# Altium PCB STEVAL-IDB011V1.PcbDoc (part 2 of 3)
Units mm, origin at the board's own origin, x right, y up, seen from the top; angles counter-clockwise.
Board outline 80.36 x 54.03 mm, 4 copper layers (Top Layer, Mid-Layer 1, Mid-Layer 2, Bottom Layer), stack 1.697 mm thick; 155 components, 122 nets, 506 pads, 646 vias.

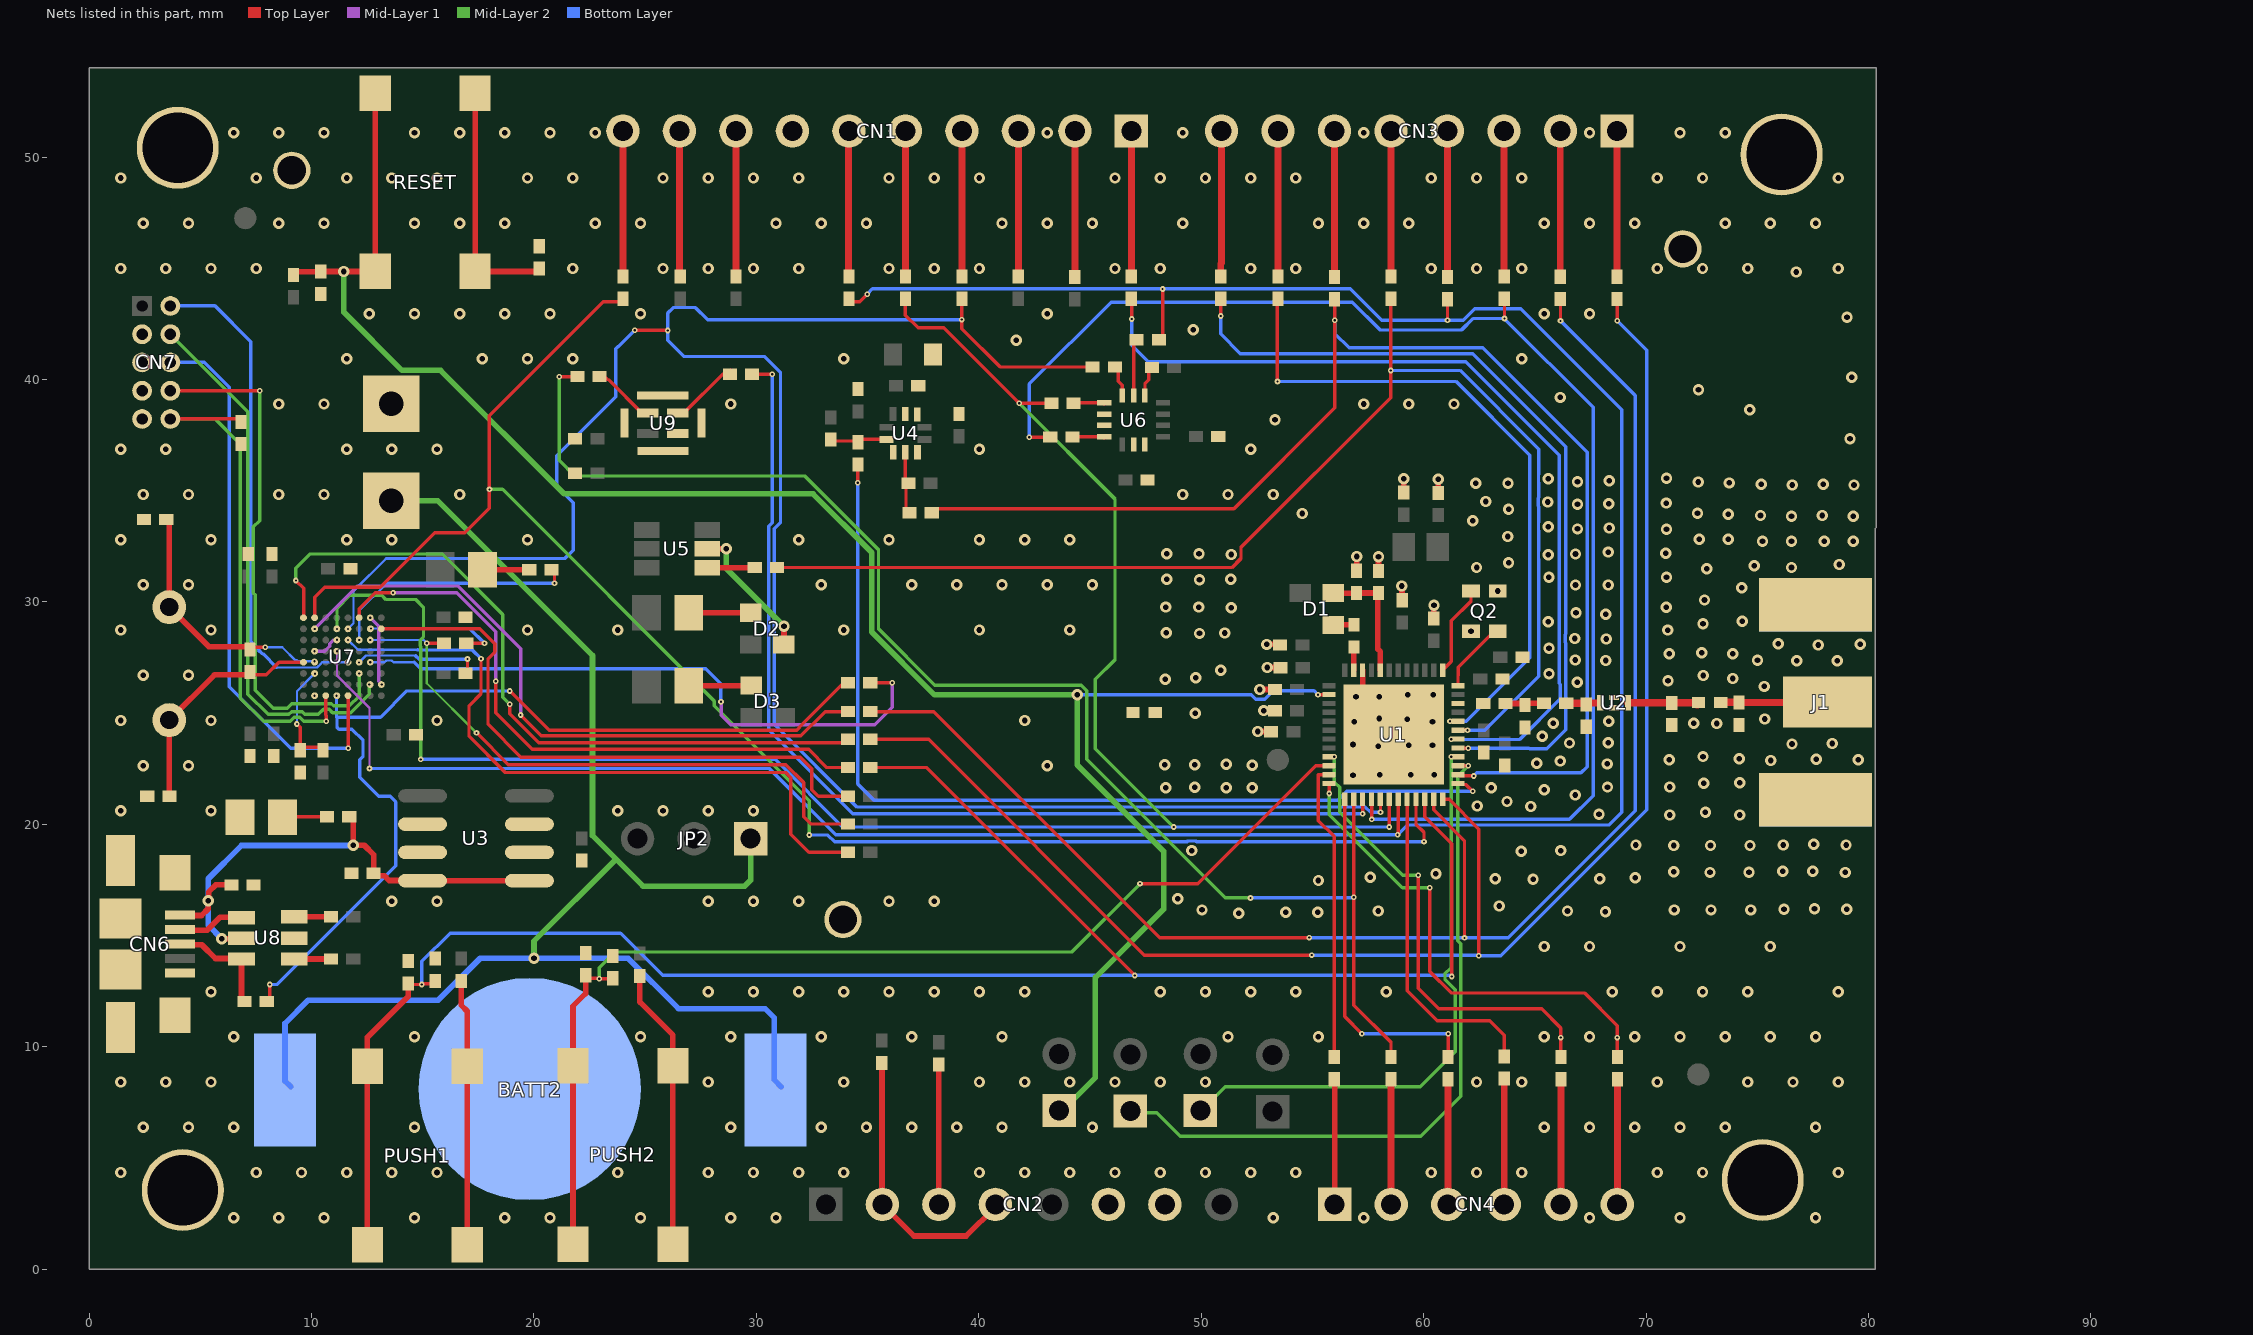
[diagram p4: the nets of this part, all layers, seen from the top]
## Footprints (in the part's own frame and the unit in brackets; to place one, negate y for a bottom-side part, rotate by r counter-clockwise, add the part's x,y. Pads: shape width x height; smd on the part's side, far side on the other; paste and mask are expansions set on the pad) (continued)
PCBCOMPONENT_1 [mil]
  round 12 smd paste+0 mask+0: A1(68.95,-68.95) A2(49.25,-68.95) A3(29.55,-68.95) A4(9.85,-68.95) A5(-9.85,-68.95) A6(-29.55,-68.95) A7(-49.25,-68.95) A8(-68.95,-68.95) B1(68.95,-49.25) B2(49.25,-49.25) B3(29.55,-49.25) B4(9.85,-49.25) B5(-9.85,-49.25) B6(-29.55,-49.25) B7(-49.25,-49.25) B8(-68.95,-49.25) C1(68.95,-29.55) C2(49.25,-29.55) C3(29.55,-29.55) C4(9.85,-29.55) C5(-9.85,-29.55) C6(-29.55,-29.55) C7(-49.25,-29.55) C8(-68.95,-29.55) D1(68.95,-9.85) D2(49.25,-9.85) D3(29.55,-9.85) D4(9.85,-9.85) D5(-9.85,-9.85) D6(-29.55,-9.85) D7(-49.25,-9.85) D8(-68.95,-9.85) E1(68.95,9.85) E2(49.25,9.85) E3(29.55,9.85) E4(9.85,9.85) E5(-9.85,9.85) E6(-29.55,9.85) E7(-49.25,9.85) E8(-68.95,9.85) F1(68.95,29.55) F2(49.25,29.55) F3(29.55,29.55) F4(9.85,29.55) F5(-9.85,29.55) F6(-29.55,29.55) F7(-49.25,29.55) F8(-68.95,29.55) G1(68.95,49.25) G2(49.25,49.25) G3(29.55,49.25) G4(9.85,49.25) G5(-9.85,49.25) G6(-29.55,49.25) G7(-49.25,49.25) G8(-68.95,49.25) H1(68.95,68.95) H2(49.25,68.95) H3(29.55,68.95) H4(9.85,68.95) H5(-9.85,68.95) H6(-29.55,68.95) H7(-49.25,68.95) H8(-68.95,68.95)
  silkscreen extent -98,-97 98,97, body extent -75,-75 75,75, height 20
QFN48_6X6 [mm]
  rect 0.599x0.24 smd: 1(-2.61,1.9) 2(-2.61,1.5) 3(-2.61,1.1) 4(-2.61,0.7) 5(-2.61,0.3) 6(-2.61,-0.1) 7(-2.61,-0.5) 8(-2.61,-0.9) 9(-2.61,-1.3) 10(-2.61,-1.7) 11(-2.61,-2.1) 12(-2.61,-2.5) 25(3.19,-2.5) 26(3.19,-2.1) 27(3.19,-1.7) 28(3.19,-1.3) 29(3.19,-0.9) 30(3.19,-0.5) 31(3.19,-0.1) 32(3.19,0.3) 33(3.19,0.7) 34(3.19,1.1) 35(3.19,1.5) 36(3.19,1.9)
  rect 0.24x0.599 smd: 13(-1.9,-3.19) 14(-1.5,-3.19) 15(-1.1,-3.19) 16(-0.7,-3.19) 17(-0.3,-3.19) 18(0.1,-3.19) 19(0.5,-3.19) 20(0.9,-3.19) 21(1.3,-3.19) 22(1.7,-3.19) 23(2.1,-3.19) 24(2.5,-3.19) 37(2.5,2.61) 38(2.1,2.61) 39(1.7,2.61) 40(1.3,2.61) 41(0.9,2.61) 42(0.5,2.61) 43(0.1,2.61) 44(-0.3,2.61) 45(-0.7,2.61) 46(-1.1,2.61) 47(-1.5,2.61) 48(-1.9,2.61)
  rect 4.499x4.499 smd: 49(0.3,-0.3)
  body extent -2.91,-3.49 3.49,2.91, height 0.51
QUARZO [mil]
  round 60 hole 32: 1(0,0) 2(200,0)
  silkscreen extent -99,-94 299,94, body extent -103,-98 303,98, height 80
"SMA Johonson 142-0701-841" [mm] "50 Ohms, SMA Jack Receptacle, Edge Mount, .25µm Gold (Au) Plating"
  rect 4x2.29 smd paste-4 mask+0: 1(0,0)
  rect 5.08x2.415 smd paste-4 mask+0: 2(0.54,4.383) 2(0.54,-4.383)
  rect 5.05x2.415 smd far side paste-4 mask+0: 2(0.54,4.383)
  rect 5.08x2.415 smd far side paste-4 mask+0: 2(0.54,-4.383)
  silkscreen extent -11.68,-4.7 -2.29,4.57, body extent -13.29,-4.77 2.25,4.76, height 8.5
"SMD _LED" [mm]
  rect 1.3x1.6 smd: 1(0.948,0.006) 2(-0.952,0.006)
  silkscreen extent -2.13,-1.14 2,1.16, body extent -1.52,-0.64 1.52,0.64, height 1.27
SO8_N [mm] "SOIC, 8-Leads, Body 4.9x3.9mm, Pitch 1.27mm, IPC Medium Density"
  oval 2.2x0.6 smd: 1(-2.4,1.905) 2(-2.4,0.635) 3(-2.4,-0.635) 4(-2.4,-1.905) 5(2.4,-1.905) 6(2.4,-0.635) 7(2.4,0.635) 8(2.4,1.905)
  silkscreen extent -2.52,-2.5 0.9,2.88, body extent -1.95,-2.45 1.95,2.45, height 1.75
SOT23-6L_S [mil]
  rect 23.6x47.23 smd: 1(-37,-42.12) 2(0,-42.12) 3(37.8,-42.12) 4(36.22,51.18) 5(0,51.17) 6(-37,51.17)
  silkscreen extent -78,-55 55,22, body extent -49,-66 50,75, height 20
stlogo [mm]
TESTP [mil]
  round 66 hole 50: 1(-50,100)

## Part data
BATT2: library part "Battery holder_0"
C1 C2 C3 C4 C5 C6 C7 C8 C9 C10 C11 C12 C13 C14 C15 C16 C17 C18 C19 C27 C28 C30 C31 C32 C33 C34 C35 C36 C39 C42 C43: library part "MURATA GRM36"
C20 C21 C22 C23 C24 C25 C26 C29 C37 C38 C40 C41: library part C, PSpiceTemplate="C^@REFDES %1 %2 ?TOLERANCE[]C^@REFDES[] @VALUE ?IC/IC{}@IC/ ?TOLERANCE[]\n.model C^@REFDES CAP C{}1 DEV{}@TOLERANCE%[]"
CN6: library part "USB micro B_0"
CN7: library part CON10AP
D1 D2 D3: library part DEV3L_0
DL3 DL4: library part Diodo_led
J1: library part SMA_Molex, "50 Ohms, SMA Jack Receptacle, Edge Mount, .25µm Gold (Au) Plating", Manufacturer=Molex
JP1 JP3 JP4 JP5: library part Buzzer
L1 L2 L3 L4: library part IND_short
PUSH1 PUSH2 RESET: library part SWITCH-1
Q1: library part QUARZO
Q2: library part NX3225SA
R1 R2 R3 R4 R5 R6 R7 R8 R9 R10 R11 R12 R13 R14 R15 R16 R17 R18 R19 R20 R21 R22 R23 R24 R25 R26 R27 R28 R30 R31 R32 R33 R35 R37 R38 R39 R41 R42 R43 R44 R45 R46 R47 R48 R49 R50 R51 R52 R53 R54 R55 R56 R57 R58 R59 R60 R61: library part R_Dup1, PSpiceTemplate="R^@REFDES %1 %2 ?TOLERANCE[]R^@REFDES[] @VALUE  ?TOLERANCE[]\n.model R^@REFDES RES R{}1 DEV{}@TOLERANCE%[]"
R29 R34 R36 R40: library part R
ST1: library part STlogo
TP1 TP2 TP3 TP4: library part "T POINT R"
U1: library part BlueNRG-LP_QFN48_0
U2: library part DLF162500LT
U3: library part KF15BD, "Very Low Drop Voltage Regulator with Inhibit", Package="SOT-23-5 STMicroelectronics"
U4: library part LPS25HB
U7: library part STM32F10XRXY, "No Description Available"
U8: library part USBUFxxW6_0
U9: library part MP34DT05-A_0
X1: library part QUARZO_Dup1

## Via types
v1: diameter 0.508, hole 0.254, Top Layer to Bottom Layer, tented both sides, 518 vias
v2: diameter 0.254, hole 0.102, Top Layer to Bottom Layer, tented both sides, 128 vias

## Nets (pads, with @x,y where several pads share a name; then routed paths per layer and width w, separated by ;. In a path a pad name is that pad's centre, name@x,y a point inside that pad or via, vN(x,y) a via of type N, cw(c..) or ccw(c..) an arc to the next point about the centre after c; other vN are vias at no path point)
BLE_RSTN: C20.2 JP5.1 R26.2 RESET.3 RESET.4 U1.38 | length 89.7
  Top Layer w0.102: R26.2@9.195,44.831 R26.2@9.212,44.848 ; C20.2@10.414,44.848 C20.2@10.422,44.856 ; RESET.4@12.866,44.856 RESET.4@12.867,44.858
  Top Layer w0.152: v2(55.251,25.833) 55.252,25.834 55.744,25.834 U1.38@55.746,25.836
  Top Layer w0.254: R26.2@9.212,44.848 C20.2@10.414,44.848 ; C20.2@10.422,44.856 v1(11.455,44.856) ; v1@11.457,44.858 11.459,44.856 RESET.4@12.866,44.856 ; RESET.4@12.867,44.858 RESET.3@12.867,52.868
  Mid-Layer 2 w0.254: v1(11.455,44.856) 11.455,43.029 14.073,40.411 15.809,40.411 21.364,34.856 32.555,34.856 35.189,32.222 35.189,28.651 38.019,25.822 v1(44.422,25.822) 44.422,22.68 48.316,18.786 48.316,16.187 45.242,13.114 45.242,8.616 JP5.1@43.675,7.048
  Bottom Layer w0.152: v1(44.422,25.822) 44.433,25.833 52.246,25.833 52.45,25.629 52.866,25.629 53.247,26.01 55.074,26.01 v2(55.251,25.833)
BLE_SWCLK: JP3.1 U1.16 | length 26.5
  Top Layer w0.152: v2@61.24,23.037 U1.16@61.547,23.037
  Mid-Layer 2 w0.152: JP3.1@49.949,7.074 51.084,8.209 59.855,8.209 61.417,9.771 61.417,12.574 60.96,13.031 60.96,13.283 61.239,13.563 v2(61.239,23.038)
BLE_SWDIO: JP4.1 U1.15 | length 31.6
  Top Layer w0.152: U1.15@61.547,22.636 61.549,22.634 61.999,22.634 v2(62.001,22.631)
  Mid-Layer 2 w0.152: JP4.1@46.838,7.036 48.006,7.036 49.06,5.982 59.873,5.982 61.671,7.78 61.671,14.631 61.532,14.77 61.532,22.162 v2(62.001,22.631)
  Bottom Layer w0.152: v2@62.001,22.611 v2(62.001,22.631)
BOOT0: CN7.10 R58.2 U7.A6 | length 23.8
  Top Layer w0.152: CN7.10@3.658,38.227 R58.2@6.833,38.227 ; U7.A6@10.643,25.786 10.643,24.919 10.668,24.894 v2(10.668,24.638)
  Mid-Layer 2 w0.152: CN7.10@3.658,38.227 5.664,38.227 6.807,37.084 6.807,25.679 7.849,24.638 9.043,24.638 9.221,24.816 9.473,24.816 9.651,24.638 v2(10.668,24.638)
DM: CN6.2 U8.4 | length 2.9
  Top Layer w0.254: CN6.2@4.293,15.24 5.309,15.24 5.893,15.824 6.706,15.824 U8.4@6.853,15.677
DP: CN6.3 R43.2 U8.6 | length 4.7
  Top Layer w0.254: CN6.3@4.293,14.59 5.069,14.59 5.69,13.97 6.701,13.97 6.858,13.813 R43.2@6.858,12.04
DP-CON: R43.1 R59.2 U7.A5 | length 43.1
  Top Layer w0.152: v2@8.125,12.802 v2(8.128,12.799) R43.1@8.128,12.04 ; v2(18.92,25.997) 20.686,24.232 31.823,24.232 31.933,24.341 31.933,24.376 33.922,26.365 R59.2@33.985,26.365
  Bottom Layer w0.152: v2(8.128,12.799) 8.448,12.799 13.792,18.143 13.792,21.007 13.539,21.26 13.03,21.26 12.167,22.123 12.167,22.911 12.319,23.063 12.319,23.774 11.811,24.282 11.237,24.282 11.148,24.372 11.148,24.816 ; v2(11.125,25.781) 11.125,24.839 11.148,24.816 ; v2(18.92,25.997) 14.288,25.997 13.107,24.816 11.148,24.816
GND: BATT1.2 BATT2.3 C17.1 C19.1 C20.1 C21.1 C22.1 C23.1 C24.1 C25.1 C26.1 C27.2 C28.2 C29.2 C31.1 C32.1 C33.1 C34.1 C35.1 C36.1 C37.1 C38.1 C39.1 C40.1 C41.1 CN1.7 CN2.6 CN2.7 CN6.5 CN6.6 CN6.7 CN6.8 CN6.9 CN6.10 CN6.11 CN7.3 CN7.5 CN7.7 CN7.9 DL1.2 L2.1 R28.2 R31.2 R32.2 R52.1 R58.1 TP1.1 TP2.1 TP3.1 U3.2 U3.3 U3.6 U3.7 U4.3 U4.5 U4.8 U4.9 U6.2 U6.3 U6.6 U6.7 U7.A7 U7.B1 U7.E7 U7.F5 U7.H2 U8.2 U9.2 U9.5 U9.6 U9.7 U9.8 V1.1 V2.1 V3.1 V4.1 | length 5.2
  Top Layer w0.102: U9.7@25.806,36.792 U9.7@26.467,36.792
  Mid-Layer 1 w0.152: v2(10.135,27.788) 10.592,27.788 10.82,28.016 10.82,28.118 10.979,28.276 11.131,28.276 v2(11.151,28.296) ; v2(12.649,29.286) 13.03,28.905 13.03,26.429 13.157,26.302 v2(13.157,26.289)
  other v1: 6.502,2.32 8.534,2.32 10.566,2.32 14.63,2.32 18.694,2.32 20.726,2.32 24.79,2.32 28.854,2.32 30.886,2.32 53.238,2.32 57.302,2.32 67.462,2.32 71.526,2.32 77.622,2.32 1.422,4.352 7.518,4.352 9.55,4.352 11.582,4.352 13.614,4.352 15.646,4.352 23.774,4.352 27.838,4.352 29.87,4.352 31.902,4.352 33.934,4.352 40.03,4.352 42.062,4.352 44.094,4.352 46.126,4.352 48.158,4.352 50.19,4.352 52.222,4.352 54.254,4.352 60.35,4.352 62.382,4.352 64.414,4.352 70.51,4.352 72.542,4.352 78.638,4.352 2.438,6.384 4.47,6.384 6.502,6.384 14.63,6.384 28.854,6.384 32.918,6.384 34.95,6.384 36.982,6.384 39.014,6.384 41.046,6.384 45.11,6.384 65.43,6.384 67.462,6.384 69.494,6.384 71.526,6.384 73.558,6.384 77.622,6.384 1.422,8.416 3.454,8.416 5.486,8.416 27.838,8.416 33.934,8.416 40.03,8.416 42.062,8.416 44.094,8.416 46.126,8.416 48.158,8.416 50.19,8.416 62.382,8.416 64.414,8.416 70.51,8.416 74.574,8.416 76.606,8.416 78.638,8.416 6.502,10.448 14.63,10.448 24.79,10.448 28.854,10.448 32.918,10.448 36.982,10.448 41.046,10.448 51.206,10.448 55.27,10.448 65.43,10.448 67.462,10.448 69.494,10.448 71.526,10.448 73.558,10.448 75.59,10.448 77.622,10.448 5.486,12.48 27.838,12.48 29.87,12.48 31.902,12.48 33.934,12.48 35.966,12.48 37.998,12.48 40.03,12.48 42.062,12.48 48.158,12.48 50.19,12.48 52.222,12.48 54.254,12.48 58.318,12.48 68.478,12.48 70.51,12.48 72.542,12.48 74.574,12.48 78.638,12.48 65.43,14.512 67.462,14.512 71.526,14.512 75.59,14.512 13.614,16.544 15.646,16.544 27.838,16.544 29.87,16.544 31.902,16.544 35.966,16.544 37.998,16.544 1.422,20.608 5.486,20.608 23.774,20.608 25.806,20.608 27.838,20.608 29.87,20.608 2.438,22.64 4.47,22.64 43.078,22.64 1.422,24.672 5.486,24.672 15.646,24.672 42.062,24.672 2.438,26.704 4.47,26.704 1.422,28.736 5.486,28.736 19.71,28.736 23.774,28.736 33.934,28.736 40.03,28.736 44.094,28.736 2.438,30.768 4.47,30.768 32.918,30.768 36.982,30.768 39.014,30.768 41.046,30.768 43.078,30.768 45.11,30.768 1.422,32.8 5.486,32.8 11.582,32.8 13.614,32.8 19.71,32.8 31.902,32.8 35.966,32.8 40.03,32.8 42.062,32.8 44.094,32.8 54.546,33.978 2.438,34.832 4.47,34.832 8.534,34.832 10.566,34.832 16.662,34.832 49.174,34.832 51.206,34.832 53.238,34.832 1.422,36.864 3.454,36.864 11.582,36.864 13.614,36.864 15.646,36.864 40.03,36.864 52.222,36.864 79.167,37.341 53.319,38.189 74.665,38.639 8.534,38.896 10.566,38.896 28.854,38.896 57.302,38.896 59.334,38.896 61.366,38.896 66.137,39.195 72.361,39.539 79.246,40.095 11.582,40.928 17.678,40.928 19.71,40.928 21.742,40.928 33.934,40.928 64.414,40.928 41.692,41.764 49.637,42.241 79.035,42.797 12.598,42.96 14.63,42.96 16.662,42.96 18.694,42.96 20.726,42.96 24.79,42.96 43.078,42.96 65.43,42.96 67.462,42.96 76.757,44.836 1.422,44.992 3.454,44.992 5.486,44.992 7.518,44.992 21.742,44.992 25.806,44.992 27.838,44.992 29.87,44.992 31.902,44.992 35.966,44.992 37.998,44.992 40.03,44.992 46.126,44.992 48.158,44.992 52.222,44.992 54.254,44.992 60.35,44.992 62.382,44.992 64.414,44.992 70.51,44.992 72.542,44.992 74.574,44.992 78.638,44.992 2.438,47.024 4.47,47.024 8.534,47.024 10.566,47.024 14.63,47.024 16.662,47.024 18.694,47.024 22.758,47.024 24.79,47.024 30.886,47.024 32.918,47.024 34.95,47.024 41.046,47.024 43.078,47.024 45.11,47.024 49.174,47.024 55.27,47.024 57.302,47.024 59.334,47.024 65.43,47.024 67.462,47.024 69.494,47.024 73.558,47.024 75.59,47.024 77.622,47.024 1.422,49.056 7.518,49.056 11.582,49.056 13.614,49.056 15.646,49.056 19.71,49.056 21.742,49.056 25.806,49.056 27.838,49.056 29.87,49.056 31.902,49.056 35.966,49.056 37.998,49.056 40.03,49.056 46.126,49.056 48.158,49.056 50.19,49.056 52.222,49.056 54.254,49.056 60.35,49.056 62.382,49.056 64.414,49.056 70.51,49.056 72.542,49.056 78.638,49.056 6.502,51.088 8.534,51.088 10.566,51.088 14.63,51.088 16.662,51.088 18.694,51.088 20.726,51.088 22.758,51.088 43.078,51.088 49.174,51.088 57.302,51.088 67.462,51.088 71.526,51.088 73.558,51.088
  other v2: 10.135,25.781
GND_RF: C1.1 C2.1 C3.1 C4.1 C5.1 C6.1 C7.1 C8.1 C9.1 C10.1 C11.1 C12.1 C13.1 C14.1 C15.1 C16.1 C18.1 C42.1 C43.1 J1.2 L2.2 Q2.2 Q2.4 U1.34 U1.49 U2.2 U2.4 | length 9.9
  Top Layer w0.152: v1(52.812,25.116) 53.302,25.116 C13.1@53.312,25.105 ; C12.1@53.134,24.178 C12.1@53.144,24.168 ; C8.1@53.528,28.09 C8.1@53.551,28.067 ; C9.1@53.551,27.051 C9.1@53.564,27.038 ; C3.1@56.981,31.404 C3.1@56.992,31.415 ; U1.49@57.257,25.436 U1.49@58.656,24.036
  Top Layer w0.254: v1(52.542,24.178) C12.1@53.134,24.178 ; v1(52.629,26.06) C15.1@53.289,26.06 ; v1(52.949,28.09) C8.1@53.528,28.09 ; v1(52.972,27.051) C9.1@53.551,27.051 ; C3.1@56.992,31.415 v1(56.992,32.04) ; U1.49@57.257,25.436 U1.34@57.257,26.927 ; C4.1@57.971,31.397 v1(57.971,32.034) ; v1(59.021,30.716) 59.028,30.709 59.028,30.218 C7.1@59.035,30.211 ; C2.1@59.108,34.92 v1(59.108,35.537) ; C16.1@60.454,29.388 60.461,29.394 60.461,29.838 v1(60.467,29.845) ; C1.1@60.653,34.904 v1(60.653,35.522)
  other v1: 51.689,16.002 53.797,16.053 55.245,16.053 68.174,16.078 57.963,16.104 66.472,16.104 50.038,16.154 71.272,16.154 72.923,16.154 74.701,16.154 76.2,16.18 79.019,16.18 77.572,16.205 63.398,16.332 48.946,16.662 55.27,17.475 64.922,17.526 63.221,17.551 67.92,17.551 69.52,17.602 57.607,17.628 60.554,17.78 72.878,17.84 78.95,17.84 71.24,17.868 74.627,17.854 76.141,17.895 77.491,17.895 64.389,18.796 49.581,18.821 66.167,18.821 71.247,19.05 72.898,19.05 74.676,19.05 69.545,19.075 76.175,19.075 78.994,19.075 77.546,19.101 71.069,20.422 74.219,20.422 67.883,20.455 72.669,20.549 64.811,20.802 62.418,20.827 63.748,21.025 66.817,21.323 65.421,21.551 48.412,21.641 51.13,21.641 52.299,21.641 63.043,21.648 49.708,21.666 68.265,21.676 71.07,21.679 72.593,21.844 74.219,21.869 56.826,22.208 58.025,22.23 59.425,22.236 60.48,22.236 52.299,22.657 48.362,22.682 49.708,22.682 51.13,22.708 68.262,22.718 65.09,22.753 66.147,22.845 75.6,22.869 71.047,22.903 79.535,22.899 77.657,22.926 74.188,22.949 72.562,23.047 57.964,23.518 59.336,23.551 60.402,23.557 56.826,23.59 76.564,23.614 78.367,23.636 66.562,23.655 68.301,23.663 65.334,23.96 73.174,24.532 65.826,24.542 72.147,24.547 60.397,24.608 56.876,24.619 68.33,24.632 59.264,24.724 75.34,24.736 57.999,24.762 49.733,24.994 56.958,25.743 57.999,25.734 60.435,25.823 59.284,25.832 75.31,26.202 66.906,26.389 70.989,26.457 48.387,26.518 73.894,26.555 49.759,26.594 72.577,26.694 65.641,26.767 50.876,26.924 68.189,27.366 76.78,27.355 78.593,27.355 66.817,27.391 75.011,27.378 71.039,27.674 73.894,27.674 72.505,27.713 65.638,27.914 77.736,28.062 79.637,28.103 75.941,28.114 68.214,28.331 66.792,28.357 49.926,28.585 48.428,28.611 51.054,28.6 62.13,28.689 70.981,28.735 72.562,29.021 65.608,29.108 74.331,29.135 68.189,29.449 66.853,29.515 51.359,29.743 70.904,29.757 48.412,29.769 49.886,29.769 72.63,30.087 63.33,30.489 74.297,30.631 66.827,30.759 68.301,30.759 49.926,30.998 48.453,31.024 51.333,31.013 70.923,31.107 65.634,31.115 72.732,31.493 62.382,31.547 76.541,31.55 74.864,31.629 78.684,31.686 63.82,31.76 65.598,32.116 51.359,32.131 48.453,32.167 49.901,32.167 66.827,32.156 70.884,32.188 68.308,32.241 75.233,32.726 76.536,32.728 78.01,32.726 79.314,32.728 72.397,32.822 73.701,32.824 63.779,32.944 70.923,33.268 66.919,33.283 68.346,33.322 65.598,33.386 62.205,33.655 76.536,33.847 79.314,33.847 75.147,33.885 77.925,33.885 73.701,33.943 72.312,33.982 63.82,34.173 66.919,34.392 68.327,34.421 70.904,34.444 65.583,34.493 62.789,34.519 76.575,35.255 79.353,35.255 75.186,35.293 77.964,35.293 62.347,35.342 63.795,35.342 73.74,35.351 72.351,35.39 66.919,35.407 68.346,35.443 65.598,35.545 70.923,35.563
GREEN: D2.3 U5.5 | length 6.2
  Top Layer w0.254: U5.5@27.79,32.385 v1(28.651,32.385) ; D2.3@31.242,28.092 v1(31.242,28.905)
  Mid-Layer 2 w0.254: v1(28.651,32.385) 28.651,31.496 v1(31.242,28.905)
JTCK: CN7.4 U7.B2 | length 24.5
  Mid-Layer 2 w0.152: CN7.4@3.658,42.037 7.137,38.557 7.137,25.857 8.052,24.943 8.989,24.943 9.116,25.07 9.579,25.07 9.706,24.943 10.313,24.943 10.542,25.171 10.794,25.171 10.947,25.019 11.76,25.019 12.598,25.857 v2(12.598,26.289)
JTDI: CN7.8 U7.C3 | length 24
  Top Layer w0.152: CN7.8@3.658,39.497 v2(7.671,39.497)
  Mid-Layer 2 w0.152: v2(7.671,39.497) 7.671,33.655 7.391,33.376 7.391,30.4 7.468,30.324 7.468,26.035 8.28,25.222 8.909,25.222 9.112,25.425 10.899,25.425 10.999,25.326 11.708,25.326 12.149,25.767 v2(12.149,26.787)
JTDO: CN7.6 U7.A4 | length 25.4
  Top Layer w0.102: v2@11.648,23.429 v2(11.659,23.419)
  Top Layer w0.152: v2@11.648,23.429 U7.A4@11.648,25.786
  Bottom Layer w0.152: CN7.6@3.658,40.767 5.182,40.767 6.299,39.649 6.299,26.187 9.068,23.419 v2(11.659,23.419)
JTMS: CN7.2 U7.D4 | length 22.7
  Bottom Layer w0.102: 8.444,27.051 10.25,27.051 10.414,27.215 10.414,27.217 10.484,27.287 v2(11.648,27.287)
  Bottom Layer w0.152: CN7.2@3.658,43.307 5.664,43.307 7.264,41.707 7.264,28.231 7.62,27.875 7.62,27.839 7.799,27.661 7.834,27.661 8.444,27.051
NetBATT1_1: BATT1.1 BATT2.1 BATT2.2 JP2.1 | length 66.7
  Mid-Layer 2 w0.152: BATT1.1@13.589,34.544 BATT1.1@13.846,34.287
  Mid-Layer 2 w0.254: BATT1.1@13.846,34.287 14.369,34.287 14.625,34.544 15.682,34.544 22.635,27.591 22.635,19.494 24.908,17.221 29.477,17.221 29.743,17.487 JP2.1@29.743,19.355 JP2.1@29.743,19.406 ; v1(20.008,13.98) 20.008,14.75 23.658,18.4
  Bottom Layer w0.254: BATT2.2@9.075,8.204 8.814,8.465 8.814,11.054 9.85,12.09 15.697,12.09 17.587,13.98 v1(20.008,13.98) 24.237,13.98 26.502,11.714 30.396,11.714 30.81,11.3 30.81,8.511 BATT2.1@31.117,8.204
NetC3_2: C3.2 C4.2 D1.1 U1.32 | length 5.6
  Top Layer w0.152: C3.2@56.972,30.395 C3.2@56.981,30.404 ; C4.2@57.962,30.404 C4.2@57.97,30.396
  Top Layer w0.254: D1.1@55.946,30.395 C3.2@56.972,30.395 ; C3.2@56.981,30.404 C4.2@57.962,30.404 ; C4.2@57.97,30.396 57.945,30.371 57.945,27.877 58.057,27.765 U1.32@58.057,26.927
NetC5_2: C5.2 C30.1 L1.1 | length 1.8
  Top Layer w0.254: C30.1@63.68,25.435 64.578,25.435 64.652,25.361 64.736,25.446 L1.1@65.406,25.446
NetC6_2: C6.2 L1.2 U2.1 | length 1.2
  Top Layer w0.33: L1.2@66.642,25.446 66.645,25.443 C6.2@67.413,25.443 ; C6.2@67.453,25.457 U2.1@67.914,25.457
NetC17_2: C17.2 C29.1 CN6.1 R29.2 U3.4 U3.5 U8.5 | length 24.8
  Top Layer w0.102: CN6.1@4.089,15.92 4.218,16.049 4.376,16.049 CN6.1@4.524,15.9 ; v1(5.359,16.561) v1@5.376,16.577
  Top Layer w0.254: CN6.1@4.524,15.9 5.055,15.9 5.359,16.205 v1(5.359,16.561) ; v1@5.376,16.577 5.376,16.958 5.698,17.281 6.392,17.281 C29.1@6.401,17.272 ; v1(5.969,14.859) 6.778,14.859 U8.5@6.828,14.91 ; R29.2@11.836,20.345 11.882,20.299 v1(11.882,19.063) 12.372,19.063 12.795,18.64 C17.2@12.795,17.806 12.913,17.688 13.279,17.688 13.491,17.477 14.989,17.477 U3.4@14.997,17.469 U3.5@19.797,17.469
  Bottom Layer w0.254: v1(5.969,14.859) 5.359,15.469 v1(5.359,16.561) 5.359,17.556 6.85,19.047 v1@11.882,19.047
NetC30_2: C30.2 U1.22 | length 0
  Top Layer w0.254: C30.2@62.653,25.438 C30.2@62.654,25.439
NetC42_2: C42.2 L3.1 U2.3 | length 3.2
  Top Layer w0.33: U2.3@69.185,25.474 C42.2@71.154,25.474 ; C42.2@71.154,25.461 L3.1@72.298,25.461
  Top Layer w0.508: C42.2@71.154,25.461 C42.2@71.154,25.474 ; L3.1@72.298,25.461 72.319,25.483 L3.1@72.361,25.483
NetC43_2: C43.2 J1.1 L3.2 | length 4.8
  Top Layer w0.33: L3.2@73.361,25.483 C43.2@74.174,25.483 ; C43.2@74.181,25.475 78.14,25.475 J1.1@78.158,25.493
NetCN1_1: CN1.1 R11.2 | length 6.5
  Top Layer w0.305: R11.2@46.863,44.632 CN1.1@46.863,51.171
NetCN1_2: CN1.2 R10.2 | length 6.6
  Top Layer w0.305: R10.2@44.323,44.607 CN1.2@44.323,51.171
NetCN1_3: CN1.3 R8.2 | length 6.5
  Top Layer w0.305: R8.2@41.783,44.632 CN1.3@41.783,51.171
NetCN1_4: CN1.4 R7.2 | length 6.5
  Top Layer w0.305: R7.2@39.243,44.632 CN1.4@39.243,51.171
NetCN1_5: CN1.5 R6.2 | length 6.5
  Top Layer w0.305: R6.2@36.703,44.632 CN1.5@36.703,51.171
NetCN1_6: CN1.6 R4.2 | length 6.5
  Top Layer w0.305: R4.2@34.163,44.632 34.15,44.645 34.15,51.158 CN1.6@34.163,51.171
NetCN1_8: CN1.8 R3.2 | length 6.5
  Top Layer w0.305: R3.2@29.083,44.632 CN1.8@29.083,51.171
NetCN1_9: CN1.9 R2.2 | length 6.6
  Top Layer w0.305: CN1.9@26.543,51.171 26.543,44.671 R2.2@26.581,44.632
NetCN1_10: CN1.10 R1.2 | length 6.5
  Top Layer w0.305: R1.2@24.003,44.632 CN1.10@24.003,51.171
NetCN2_2: CN2.2 CN2.4 R5.1 | length 12.6
  Top Layer w0.254: R5.1@35.636,9.144 35.651,9.129 35.651,2.931 CN2.2@35.666,2.916 37.091,1.491 39.431,1.491 40.746,2.806 CN2.4@40.746,2.916
NetCN2_3: CN2.3 R9.1 | length 6.7
  Top Layer w0.254: CN2.3@37.8,2.916 CN2.3@38.206,2.916 R9.1@38.206,9.013 ; R9.1@38.1,9.042 R9.1@38.206,8.937
NetCN3_1: CN3.1 R24.2 | length 6.4
  Top Layer w0.305: CN3.1@68.693,51.171 68.694,51.169 68.694,44.755 R24.2@68.694,44.752
NetCN3_2: CN3.2 R22.2 | length 6.4
  Top Layer w0.305: R22.2@66.142,44.755 66.142,51.16 CN3.2@66.153,51.171
NetCN3_3: CN3.3 R20.2 | length 6.4
  Top Layer w0.152: R20.2@63.613,44.782 R20.2@63.627,44.767
  Top Layer w0.305: R20.2@63.613,44.782 CN3.3@63.613,51.171
NetCN3_4: CN3.4 R18.2 | length 6.4
  Top Layer w0.305: CN3.4@61.073,51.171 61.074,51.169 R18.2@61.074,44.742
NetCN3_5: CN3.5 R16.2 | length 6.4
  Top Layer w0.305: CN3.5@58.533,51.171 58.534,51.169 R16.2@58.534,44.767
NetCN3_6: CN3.6 R13.2 | length 6.4
  Top Layer w0.305: CN3.6@55.993,51.171 55.994,51.169 R13.2@55.994,44.742
NetCN3_7: CN3.7 R14.2 | length 6.4
  Top Layer w0.305: CN3.7@53.453,51.171 53.454,51.169 R14.2@53.454,44.767
NetCN3_8: CN3.8 R12.2 | length 6.6
  Top Layer w0.305: R12.2@50.876,44.632 50.876,45.199 50.913,45.236 CN3.8@50.913,51.171
NetCN4_1: CN4.1 R15.1 | length 5.5
  Top Layer w0.152: R15.1@55.982,8.407 R15.1@56.004,8.385
  Top Layer w0.254: CN4.1@56.004,2.916 R15.1@56.004,8.385
NetCN4_2: CN4.2 R17.1 | length 5.5
  Top Layer w0.305: R17.1@58.534,8.407 58.534,2.926 CN4.2@58.544,2.916
NetCN4_3: CN4.3 R19.1 | length 5.5
  Top Layer w0.305: CN4.3@61.084,2.916 61.092,2.924 61.092,8.4 R19.1@61.1,8.407
NetCN4_4: CN4.4 R21.1 | length 5.5
  Top Layer w0.305: CN4.4@63.624,2.916 63.626,2.917 63.626,8.432 R21.1@63.627,8.433
NetCN4_5: CN4.5 R23.1 | length 5.5
  Top Layer w0.305: CN4.5@66.164,2.916 66.172,2.924 66.172,8.4 R23.1@66.18,8.407
NetCN4_6: CN4.6 R25.1 | length 5.5
  Top Layer w0.305: CN4.6@68.704,2.916 68.712,2.924 68.712,8.4 R25.1@68.72,8.407
NetD1_2: D1.2 L4.2 | length 0.9
  Top Layer w0.254: D1.2@55.946,28.972 L4.2@56.868,28.972
NetD2_2: D2.2 DL2.2 | length 2.8
  Top Layer w0.254: DL2.2@26.95,29.515 D2.2@29.743,29.515
NetD3_2: D3.2 DL3.2 | length 2.8
  Top Layer w0.254: DL3.2@26.949,26.238 D3.2@29.769,26.238
NetDL1_1: DL1.1 R29.1 | length 1.9
  Top Layer w0.102: DL1.1@8.695,20.326 DL1.1@8.714,20.345
  Top Layer w0.152: DL1.1@8.714,20.345 R29.1@10.566,20.345
NetDL4_2: DL4.2 R61.1 | length 1.8
  Top Layer w0.254: DL4.2@17.679,31.445 19.456,31.445
NetL4_1: L4.1 U1.35 | length 1.1
  Top Layer w0.152: L4.1@56.857,27.961 L4.1@56.868,27.972
  Top Layer w0.254: U1.35@56.857,26.927 L4.1@56.857,27.961
NetQ2_1: Q2.1 U1.25 | length 4.1
  Top Layer w0.152: U1.25@60.857,26.927 61.251,27.321 61.251,29.16 62.13,30.039 Q2.1@62.13,30.489
NetQ2_3: Q2.3 U1.24 | length 3.3
  Top Layer w0.152: U1.24@61.547,26.237 61.547,26.695 61.549,26.698 61.549,27.064 63.174,28.689 Q2.3@63.33,28.689
NetR27_2: PUSH1.3 PUSH1.4 R27.2 | length 11.8
  Top Layer w0.254: R27.2@16.739,12.827 16.739,11.862 17.003,11.597 PUSH1.4@17.003,9.117 PUSH1.3@17.003,1.107
NetR28_1: R28.1 RESET.1 RESET.2 | length 10.9
  Top Layer w0.102: R28.1@20.242,44.858 R28.1@20.244,44.856
  Top Layer w0.254: RESET.1@17.357,52.868 RESET.2@17.357,44.858 R28.1@20.242,44.858
NetR30_2: PUSH2.3 PUSH2.4 R30.2 | length 12.5
  Top Layer w0.254: R30.2@24.765,13.056 24.765,12.014 26.249,10.53 PUSH2.4@26.249,9.142 PUSH2.3@26.249,1.132
NetR33_2: R33.2 R34.2 U4.2 | length 2.6
  Top Layer w0.152: R34.2@33.426,37.236 R33.2@34.493,37.236 ; R33.2@34.576,37.306 U4.2@35.846,37.306
  Top Layer w0.254: R34.2@33.35,37.16 R34.2@33.426,37.236 ; R33.2@34.493,37.236 34.569,37.313 R33.2@34.576,37.306 ; U4.2@35.846,37.306 U4.2@35.852,37.3
NetR35_2: R35.2 R36.2 U4.4 | length 2.7
  Top Layer w0.152: R36.2@36.703,35.331 U4.4@36.703,36.728 ; R35.2@36.728,34.036 R36.2@36.728,35.306
  Top Layer w0.254: R36.2@36.703,35.331 R36.2@36.728,35.306 ; R35.2@36.728,34.036 R35.2@36.754,34.011
NetR37_1: R37.1 U6.14 | length 1.4
  Top Layer w0.152: R37.1@46.279,40.538 46.279,39.929 46.457,39.751 U6.14@46.457,39.281
  Top Layer w0.254: R37.1@46.253,40.564 R37.1@46.279,40.538
NetR38_1: R38.1 U6.13 | length 2.5
  Top Layer w0.152: U6.13@46.965,39.281 R38.1@46.965,41.783
NetR39_1: R39.1 U6.12 | length 1.3
  Top Layer w0.152: U6.12@47.473,39.281 47.473,39.802 47.65,39.98 R39.1@47.65,40.538
NetR40_1: R40.1 U5.4 | length 2
  Top Layer w0.254: U5.4@27.79,31.535 27.796,31.541 29.788,31.541 R40.1@29.794,31.547
NetR41_2: R41.2 U6.1 | length 1.2
  Top Layer w0.152: R41.2@44.41,38.949 U6.1@45.642,38.949
  Top Layer w0.254: R41.2@44.399,38.938 R41.2@44.41,38.949 ; U6.1@45.642,38.949 U6.1@45.644,38.951
NetR42_2: R42.2 U6.4 | length 1.3
  Top Layer w0.152: R42.2@44.359,37.425 U6.4@45.642,37.425
  Top Layer w0.254: R42.2@44.348,37.414 R42.2@44.359,37.425 ; U6.4@45.642,37.425 U6.4@45.644,37.427
NetR45_2: R45.2 U8.1 | length 1.5
  Top Layer w0.254: U8.1@9.223,13.945 R45.2@10.744,13.945
NetR46_2: R46.2 U8.3 | length 1.5
  Top Layer w0.254: U8.3@9.223,15.845 9.226,15.847 10.742,15.847 R46.2@10.744,15.85
NetR47_2: R47.2 U7.H3 | length 27.9
  Top Layer w0.152: U7.H3@12.149,29.289 12.149,29.688 12.875,30.414 v2(13.67,30.414) ; v2(18.288,26.429) 18.288,25.016 19.929,23.376 32.355,23.376 33.175,22.555 R47.2@33.985,22.555
  Mid-Layer 1 w0.152: v2(13.67,30.414) 16.525,30.414 18.288,28.651 v2(18.288,26.429)
NetR48_2: R48.2 U7.H8 | length 33.3
  Top Layer w0.152: v2(9.301,30.963) 9.652,30.612 9.652,29.299 U7.H8@9.642,29.289 ; v2(18.913,25.397) 18.913,24.974 20.211,23.676 33.836,23.676 R48.2@33.985,23.825
  Mid-Layer 2 w0.152: v2(9.301,30.963) 9.301,31.521 9.936,32.156 15.872,32.156 18.593,29.436 18.593,25.717 v2(18.913,25.397)
NetR49_1: R49.1 U7.G7 | length 29.6
  Top Layer w0.152: v2(19.403,24.915) 20.34,23.978 32.007,23.978 33.099,25.07 R49.1@33.985,25.07
  Mid-Layer 1 w0.152: v2(10.147,28.788) 12.078,30.719 16.58,30.719 19.403,27.895 v2(19.403,24.915)
NetR50_2: R50.2 U9.4 | length 2.7
  Top Layer w0.152: R50.2@23.063,40.251 23.304,40.009 ; 23.381,39.958 24.845,38.494 U9.4@25.121,38.494
NetR51_2: R51.2 U9.3 | length 3.2
  Top Layer w0.152: U9.3@26.467,38.494 26.742,38.494 28.482,40.234 28.677,40.234 R51.2@28.854,40.411
NetR53_1: R53.1 U7.G1 | length 27.1
  Top Layer w0.152: U7.G1@13.15,28.788 17.566,28.788 18.24,28.115 18.24,27.747 17.94,27.447 17.94,24.496 19.416,23.021 31.983,23.021 32.495,22.508 32.495,21.558 32.794,21.26 R53.1@33.985,21.26
NetR54_2: R54.2 R55.2 U7.F2 | length 27.4
  Top Layer w0.152: v2(12.649,28.288) U7.F2@12.683,28.288 ; v2(15.189,28.143) R55.2@15.824,28.143 ; v2(17.422,24.112) 18.854,22.68 31.333,22.68 32.131,21.882 32.131,20.348 32.464,20.015 R54.2@33.985,20.015
  Mid-Layer 2 w0.102: v2(15.189,28.143) 15.189,26.345 v2(17.422,24.112)
  Bottom Layer w0.102: v2(12.649,28.288) 15.044,28.288 v2(15.189,28.143)
NetR55_1: R55.1 U7.G2 | length 6.1
  Top Layer w0.152: R55.1@17.094,28.143 v2(17.78,28.143)
  Bottom Layer w0.102: v2(12.675,28.804) 17.12,28.804
  Bottom Layer w0.152: 17.12,28.804 v2(17.78,28.143)
NetR56_2: R56.2 U7.F4 | length 30.6
  Top Layer w0.152: v2(17.625,27.445) 17.625,25.883 17.085,25.342 17.085,23.957 18.71,22.332 31.322,22.332 31.557,22.097 31.557,19.555 32.367,18.745 R56.2@33.985,18.745
  Bottom Layer w0.102: v2(11.648,28.288) 12.09,27.846 14.782,27.846
  Bottom Layer w0.152: 14.782,27.846 14.79,27.838 17.231,27.838 v2(17.625,27.445)
NetR59_1: R59.1 U7.D2 | length 27.8
  Top Layer w0.152: R59.1@35.255,26.365 v2(36.114,26.365)
  Mid-Layer 1 w0.152: v2(28.41,25.517) 28.425,25.502 28.425,24.902 28.842,24.486 35.334,24.486 36.114,25.265 v2(36.114,26.365)
  Bottom Layer w0.102: v2(12.649,27.287) 13.288,27.287 13.372,27.371 13.603,27.371 13.687,27.287 14.622,27.287
  Bottom Layer w0.152: 14.622,27.287 14.909,27 27.724,27 28.41,26.314 v2(28.41,25.517)
NetR60_1: R60.1 U7.D3 | length 5.7
  Top Layer w0.152: R60.1@17.018,26.848 v2(17.018,27.432)
  Top Layer w0.254: R60.1@17.018,26.848 R60.1@17.069,26.797
  Bottom Layer w0.102: v2(12.141,27.28) 12.454,27.592 14.677,27.592
  Bottom Layer w0.152: 14.677,27.592 14.837,27.432 v2(17.018,27.432)
NetR61_2: R61.2 U7.F3 | length 11.3
  Top Layer w0.152: R61.2@20.726,31.445 20.93,31.242 v2(20.93,30.836)
  Bottom Layer w0.102: v2(12.149,28.288) 12.149,29.599 13.36,30.81
  Bottom Layer w0.152: 13.36,30.81 13.386,30.836 v2(20.93,30.836)
NRST: R52.2 R57.1 U7.C7 | length 4.8
  Top Layer w0.152: v2(9.347,24.511) 9.5,24.359 9.5,23.467 9.505,23.472 R57.1@10.546,23.472
  Bottom Layer w0.102: v2(9.347,24.511) 9.347,25.987 v2@10.14,26.779
  Bottom Layer w0.152: v2@10.14,26.779 v2@10.147,26.779
  other v2: 10.16,26.772
OSC_IN: C27.1 R44.2 U7.D8 X1.2 | length 10.6
  Top Layer w0.152: R44.2@7.239,26.721 7.976,26.721 8.541,27.286 9.646,27.286 U7.D8@9.647,27.287
  Top Layer w0.254: C27.1@3.607,21.209 X1.2@3.607,24.689 5.639,26.721 R44.2@7.239,26.721
OSC_OUT: C28.1 R44.1 U7.D7 X1.1 | length 11.5
  Top Layer w0.152: R44.1@7.239,27.991 7.264,27.965 v2(7.925,27.965)
  Top Layer w0.254: C28.1@3.607,33.706 X1.1@3.607,29.769 5.385,27.991 R44.1@7.239,27.991
  Bottom Layer w0.102: v2(7.925,27.965) 8.687,27.965 9.307,27.346 9.342,27.381 9.393,27.33 v2(10.135,27.33)
PA0: R33.1 U1.13 | length 43.2
  Top Layer w0.152: v2(34.559,35.354) 34.559,36.032 R33.1@34.569,36.043 ; U1.13@61.547,21.836 61.59,21.793 61.9,21.793 v2(62.205,21.488)
  Bottom Layer w0.152: v2(34.559,35.354) 34.559,21.814 35.291,21.082 56.137,21.082 56.543,21.488 v2(62.205,21.488)
PA1: R13.1 R35.1 U1.14 | length 59
  Top Layer w0.152: R35.1@38.024,34.011 38.202,34.188 51.476,34.188 56.01,38.722 v2(56.01,42.664) 56.01,43.457 R13.1@55.994,43.472 ; U1.14@61.547,22.236 61.59,22.194 62.236,22.194 v2(62.255,22.174)
  Bottom Layer w0.152: v2(56.01,42.664) 56.01,42.057 56.647,41.42 62.664,41.42 67.351,36.733 67.351,22.596 67.076,22.321 62.394,22.321 62.255,22.182 v2(62.255,22.174)
PA4: R12.1 U1.17 | length 37
  Top Layer w0.152: R12.1@50.876,43.497 50.881,43.492 v2(50.881,42.855) ; U1.17@61.547,23.437 61.556,23.428 61.993,23.428 v2(62.001,23.419)
  Bottom Layer w0.152: v2(50.881,42.855) 50.881,42.047 51.763,41.166 62.205,41.166 66.396,36.975 66.396,28.571 66.36,28.535 66.36,28.178 66.396,28.142 66.396,27.58 66.385,27.57 66.385,27.213 66.396,27.202 66.396,24.257 65.537,23.398 64.759,23.398 64.738,23.419 v2(62.001,23.419)
PA5: R11.1 U1.18 | length 40.2
  Top Layer w0.152: R11.1@46.863,43.497 46.876,43.485 v2(46.876,42.72) ; v2(61.239,23.825) 61.245,23.831 61.541,23.831 U1.18@61.547,23.836
  Bottom Layer w0.152: v2(46.876,42.72) 46.876,41.549 47.628,40.797 61.895,40.797 66.091,36.601 66.091,26.341 66.142,26.29 66.142,25.645 64.312,23.816 61.249,23.816 v2(61.239,23.825)
PA6: R16.1 R40.2 U1.19 | length 58.2
  Top Layer w0.152: R40.2@31.064,31.547 51.385,31.547 51.791,31.952 51.791,32.451 58.524,39.184 v2(58.524,40.406) 58.524,43.487 R16.1@58.534,43.497 ; U1.19@61.547,24.236 61.549,24.234 61.974,24.234 v2(61.976,24.232)
  Bottom Layer w0.152: v2(58.524,40.406) 61.638,40.406 65.176,36.868 65.176,35.734 65.166,35.724 65.166,35.366 65.176,35.356 65.176,34.697 65.151,34.672 65.151,34.314 65.176,34.289 65.176,33.575 65.166,33.565 65.166,33.207 65.176,33.197 65.176,32.305 65.166,32.295 65.166,31.937 65.176,31.927 65.176,26.663 62.745,24.232 v2(61.976,24.232)
PA7: R14.1 U1.20 | length 30.5
  Top Layer w0.152: v2(53.429,39.911) 53.429,43.472 R14.1@53.454,43.497 ; v2@61.189,24.637 U1.20@61.547,24.636
  Bottom Layer w0.152: v2(53.429,39.911) 61.458,39.911 64.765,36.604 64.765,27.483 61.92,24.638 v2(61.189,24.638)
PA8: R24.1 R48.1 U1.12 | length 72.8
  Top Layer w0.152: R48.1@35.255,23.825 37.744,23.825 47.447,14.122 v2(54.966,14.122) ; U1.12@60.857,21.126 61.145,21.126 62.484,19.787 v2(62.484,14.097) ; R24.1@68.694,43.485 68.704,43.475 v2(68.704,42.642)
  Bottom Layer w0.152: v2(54.966,14.122) 54.978,14.11 62.471,14.11 v2(62.484,14.097) 63.475,14.097 70.028,20.65 70.028,41.318 v2(68.704,42.642)
PA9: R22.1 R49.2 U1.11 | length 71.9
  Top Layer w0.152: R49.2@35.255,25.07 37.973,25.07 48.133,14.91 v2(54.864,14.91) ; U1.11@60.457,21.126 60.452,21.121 60.452,20.65 61.837,19.265 v2(61.837,14.896) ; R22.1@66.142,43.485 66.154,43.472 v2(66.154,42.634)
  Bottom Layer w0.152: v2(54.864,14.91) 54.877,14.896 v2(61.837,14.896) 61.846,14.905 63.8,14.905 69.507,20.612 69.507,39.281 v2(66.154,42.634)
PA10: C40.2 PUSH1.1 PUSH1.2 R31.1 R47.1 U1.10 | length 86.5
  Top Layer w0.102: C40.2@14.351,12.852 C40.2@14.402,12.802 ; v2(14.961,12.802) v2@14.986,12.827
  Top Layer w0.152: C40.2@14.402,12.802 v2(14.961,12.802) ; v2@14.986,12.827 R31.1@15.57,12.827 ; R47.1@35.255,22.555 37.668,22.555 v2(47.015,13.208) ; U1.10@60.057,21.126 60.057,20.334 61.265,19.126 v2(61.265,13.157)
  Top Layer w0.254: PUSH1.1@12.513,1.107 PUSH1.2@12.513,9.117 12.513,10.43 14.351,12.268 C40.2@14.351,12.852
  Bottom Layer w0.152: v2(14.961,12.802) 14.961,13.843 16.231,15.113 23.896,15.113 25.801,13.208 v2(47.015,13.208) 61.214,13.208 v2(61.265,13.157)
PA11: R1.1 U1.9 U7.H7 | length 74.4
  Top Layer w0.152: U7.H7@10.142,29.289 10.147,29.294 10.147,30.213 10.602,30.668 13.091,30.668 15.535,33.111 16.896,33.111 17.993,34.209 17.993,38.369 23.122,43.497 R1.1@24.003,43.497 ; U1.9@59.657,21.126 59.657,19.998 60.02,19.634 v2(60.02,19.225)
  Mid-Layer 2 w0.152: v2(18.004,35.06) 18.591,35.06 28.105,25.546 28.105,25.337 32.38,21.062 v2(32.38,19.52)
  Bottom Layer w0.152: v2(32.38,19.52) 33.222,19.52 33.517,19.225 49.374,19.225 49.402,19.253 49.76,19.253 49.788,19.225 v2(60.02,19.225)
PA12: R21.2 U1.8 | length 14.6
  Top Layer w0.152: U1.8@59.257,21.126 59.257,12.524 60.604,11.176 62.967,11.176 63.627,10.516 R21.2@63.627,9.703
PA13: R4.1 R18.1 R38.2 U1.7 U7.E5 | length 124.3
  Top Layer w0.152: R4.1@34.163,43.497 34.648,43.497 v2(34.986,43.835) ; R38.2@48.235,41.783 48.265,41.813 v2(48.265,44.072) ; v2(58.831,19.533) 58.852,19.553 U1.7@58.852,21.126 ; v2(61.074,42.669) R18.1@61.074,43.472
  Mid-Layer 1 w0.102: v2(11.148,27.788) 11.148,26.698 12.611,25.235 v2(12.611,22.509)
  Mid-Layer 2 w0.152: v2(11.148,27.788) v2@11.153,27.783
  Bottom Layer w0.152: v2@12.611,22.512 30.589,22.512 33.569,19.533 v2(58.831,19.533) 59.268,19.969 68.331,19.969 68.901,20.54 68.901,38.647 64.364,43.185 62.304,43.185 61.788,42.669 v2(61.074,42.669) 58.11,42.669 56.7,44.079 48.268,44.079 v2@48.265,44.077 ; v2(34.986,43.835) 35.222,44.072 v2(48.265,44.072)
PA14: R6.1 R41.1 U1.6 U7.G5 | length 89.6
  Top Layer w0.152: R6.1@36.703,43.497 36.703,42.888 37.272,42.319 38.435,42.319 v2(41.816,38.938) R41.1@43.129,38.938 ; U1.6@58.445,21.115 58.42,21.09 58.45,21.059 v2(58.45,19.881)
  Mid-Layer 2 w0.152: v2(11.148,28.788) 11.148,29.723 11.717,30.292 13.167,30.292 13.35,30.109 14.696,30.109 15.037,29.769 15.037,28.422 14.884,28.269 14.884,28.017 14.915,27.986 14.915,22.931 v2@14.907,22.924 ; v2(41.816,38.938) 46.126,34.628 46.126,27.409 45.242,26.525 45.242,23.401 v2(48.762,19.881)
  Bottom Layer w0.152: v2(14.91,22.921) 30.848,22.921 33.889,19.881 v2(48.762,19.881) v2(58.45,19.881)
PA15: R7.1 R37.2 U1.5 U7.G4 | length 99.1
  Top Layer w0.152: v2(24.536,42.22) 24.545,42.211 26.008,42.211 v2(26.017,42.202) ; R7.1@39.243,43.497 39.233,43.487 v2(39.233,42.692) 39.233,42.286 40.955,40.564 R37.2@44.983,40.564 ; U1.5@58.057,21.126 58.064,21.118 v2(58.064,20.549)
  Bottom Layer w0.102: v2@11.648,28.798 11.895,29.045 11.895,30.488 13.36,31.953
  Bottom Layer w0.152: v2(11.648,28.788) v2@11.648,28.798 ; 13.36,31.953 21.392,31.953 21.763,32.324 21.763,34.458 21.031,35.189 21.031,36.581 23.68,39.23 23.68,41.389 23.77,41.478 23.795,41.478 v2(24.536,42.22) ; v2(39.233,42.692) 27.81,42.692 27.267,43.236 26.264,43.236 26.017,42.989 v2(26.017,42.202) 26.017,41.758 26.739,41.036 30.35,41.036 31.09,40.297 31.09,33.574 30.81,33.295 30.81,24.496 34.526,20.78 57.383,20.78 57.614,20.549 v2(58.064,20.549)
PB0: R20.1 R42.1 U1.4 | length 62
  Top Layer w0.152: v2(42.273,37.407) 43.071,37.407 R42.1@43.078,37.414 ; v2(57.663,20.223) U1.4@57.663,21.12 ; R20.1@63.627,43.497 63.635,43.49 v2(63.635,42.741)
  Bottom Layer w0.152: v2(42.273,37.407) 42.273,39.799 45.954,43.48 56.797,43.48 58.052,42.225 61.703,42.225 62.218,42.741 v2(63.635,42.741) 67.63,38.745 67.63,21.294 66.559,20.223 v2(57.663,20.223)
PB1: R51.1 U1.3 | length 45.7
  Top Layer w0.152: R51.1@29.947,40.234 29.952,40.239 v2(30.711,40.239) ; v2(57.257,20.475) U1.3@57.257,21.126
  Bottom Layer w0.152: v2(30.711,40.239) 30.711,33.555 30.556,33.4 30.556,24.251 34.332,20.475 v2(57.257,20.475)
PB2: R17.2 R50.1 U1.2 | length 64.4
  Top Layer w0.152: v2(21.138,40.127) R50.1@21.814,40.127 ; U1.2@56.857,21.126 v2(56.857,16.726) 56.857,11.876 58.534,10.198 R17.2@58.534,9.677
  Top Layer w0.254: R50.1@21.814,40.127 R50.1@21.819,40.132
  Mid-Layer 2 w0.152: v2(21.138,40.127) 21.138,36.368 21.844,35.662 32.181,35.662 35.494,32.349 35.494,28.786 38.026,26.253 44.601,26.253 44.854,26 44.854,22.929 51.09,16.693 v2(52.22,16.693)
  Bottom Layer w0.152: v2(52.22,16.693) 52.236,16.709 56.84,16.709 v2(56.857,16.726)
PB3: R19.2 U1.1 | length 15.7
  Top Layer w0.152: U1.1@56.457,21.126 56.457,11.361 v2(57.226,10.592) ; R19.2@61.1,9.677 61.112,9.69 v2(61.112,10.592)
  Bottom Layer w0.152: v2(57.226,10.592) v2(61.112,10.592)
PB4: R25.2 U1.48 | length 21.8
  Top Layer w0.152: U1.48@55.746,21.836 55.753,21.83 v2(55.753,21.387) ; v2(60.274,17.145) 60.274,13.386 61.239,12.421 67.234,12.421 68.707,10.947 v2(68.707,10.414) 68.707,9.69 R25.2@68.72,9.677
  Mid-Layer 2 w0.152: v2(55.753,21.387) 55.753,20.442 59.05,17.145 v2(60.274,17.145)
PB5: R15.2 U1.47 | length 13.3
  Top Layer w0.152: U1.47@55.746,22.236 55.269,22.236 55.269,20.169 55.982,19.456 R15.2@55.982,9.677
PB6: C41.2 PUSH2.1 PUSH2.2 R32.1 U1.46 | length 50.5
  Top Layer w0.102: v2@22.911,13.081 v2(22.936,13.056) ; C41.2@23.52,13.056 C41.2@23.546,13.081
  Top Layer w0.152: R32.1@22.327,13.081 v2@22.911,13.081 ; v2(22.936,13.056) C41.2@23.52,13.056 ; v2(47.252,17.338) 49.85,17.338 55.146,22.634 55.744,22.634 U1.46@55.746,22.636
  Top Layer w0.254: PUSH2.1@21.759,1.132 PUSH2.2@21.759,9.142 21.759,11.827 22.327,12.395 R32.1@22.327,13.081
  Mid-Layer 2 w0.152: v2(22.936,13.056) 22.936,13.564 23.635,14.262 44.176,14.262 v2(47.252,17.338)
PB7: R23.2 U1.45 | length 20.9
  Top Layer w0.152: U1.45@55.746,23.037 55.747,23.038 v2(55.982,23.038) ; v2(59.753,17.716) 59.741,17.704 59.753,17.691 59.753,12.636 60.681,11.709 65.303,11.709 66.167,10.846 v2(66.167,10.414) 66.167,9.69 R23.2@66.18,9.677
  Mid-Layer 2 w0.152: v2(55.982,23.038) 55.982,21.901 56.223,21.66 56.223,20.551 59.058,17.716 v2(59.753,17.716)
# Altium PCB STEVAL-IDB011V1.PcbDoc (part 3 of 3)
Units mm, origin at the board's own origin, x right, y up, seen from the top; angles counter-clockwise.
Board outline 80.36 x 54.03 mm, 4 copper layers (Top Layer, Mid-Layer 1, Mid-Layer 2, Bottom Layer), stack 1.697 mm thick; 155 components, 122 nets, 506 pads, 646 vias.

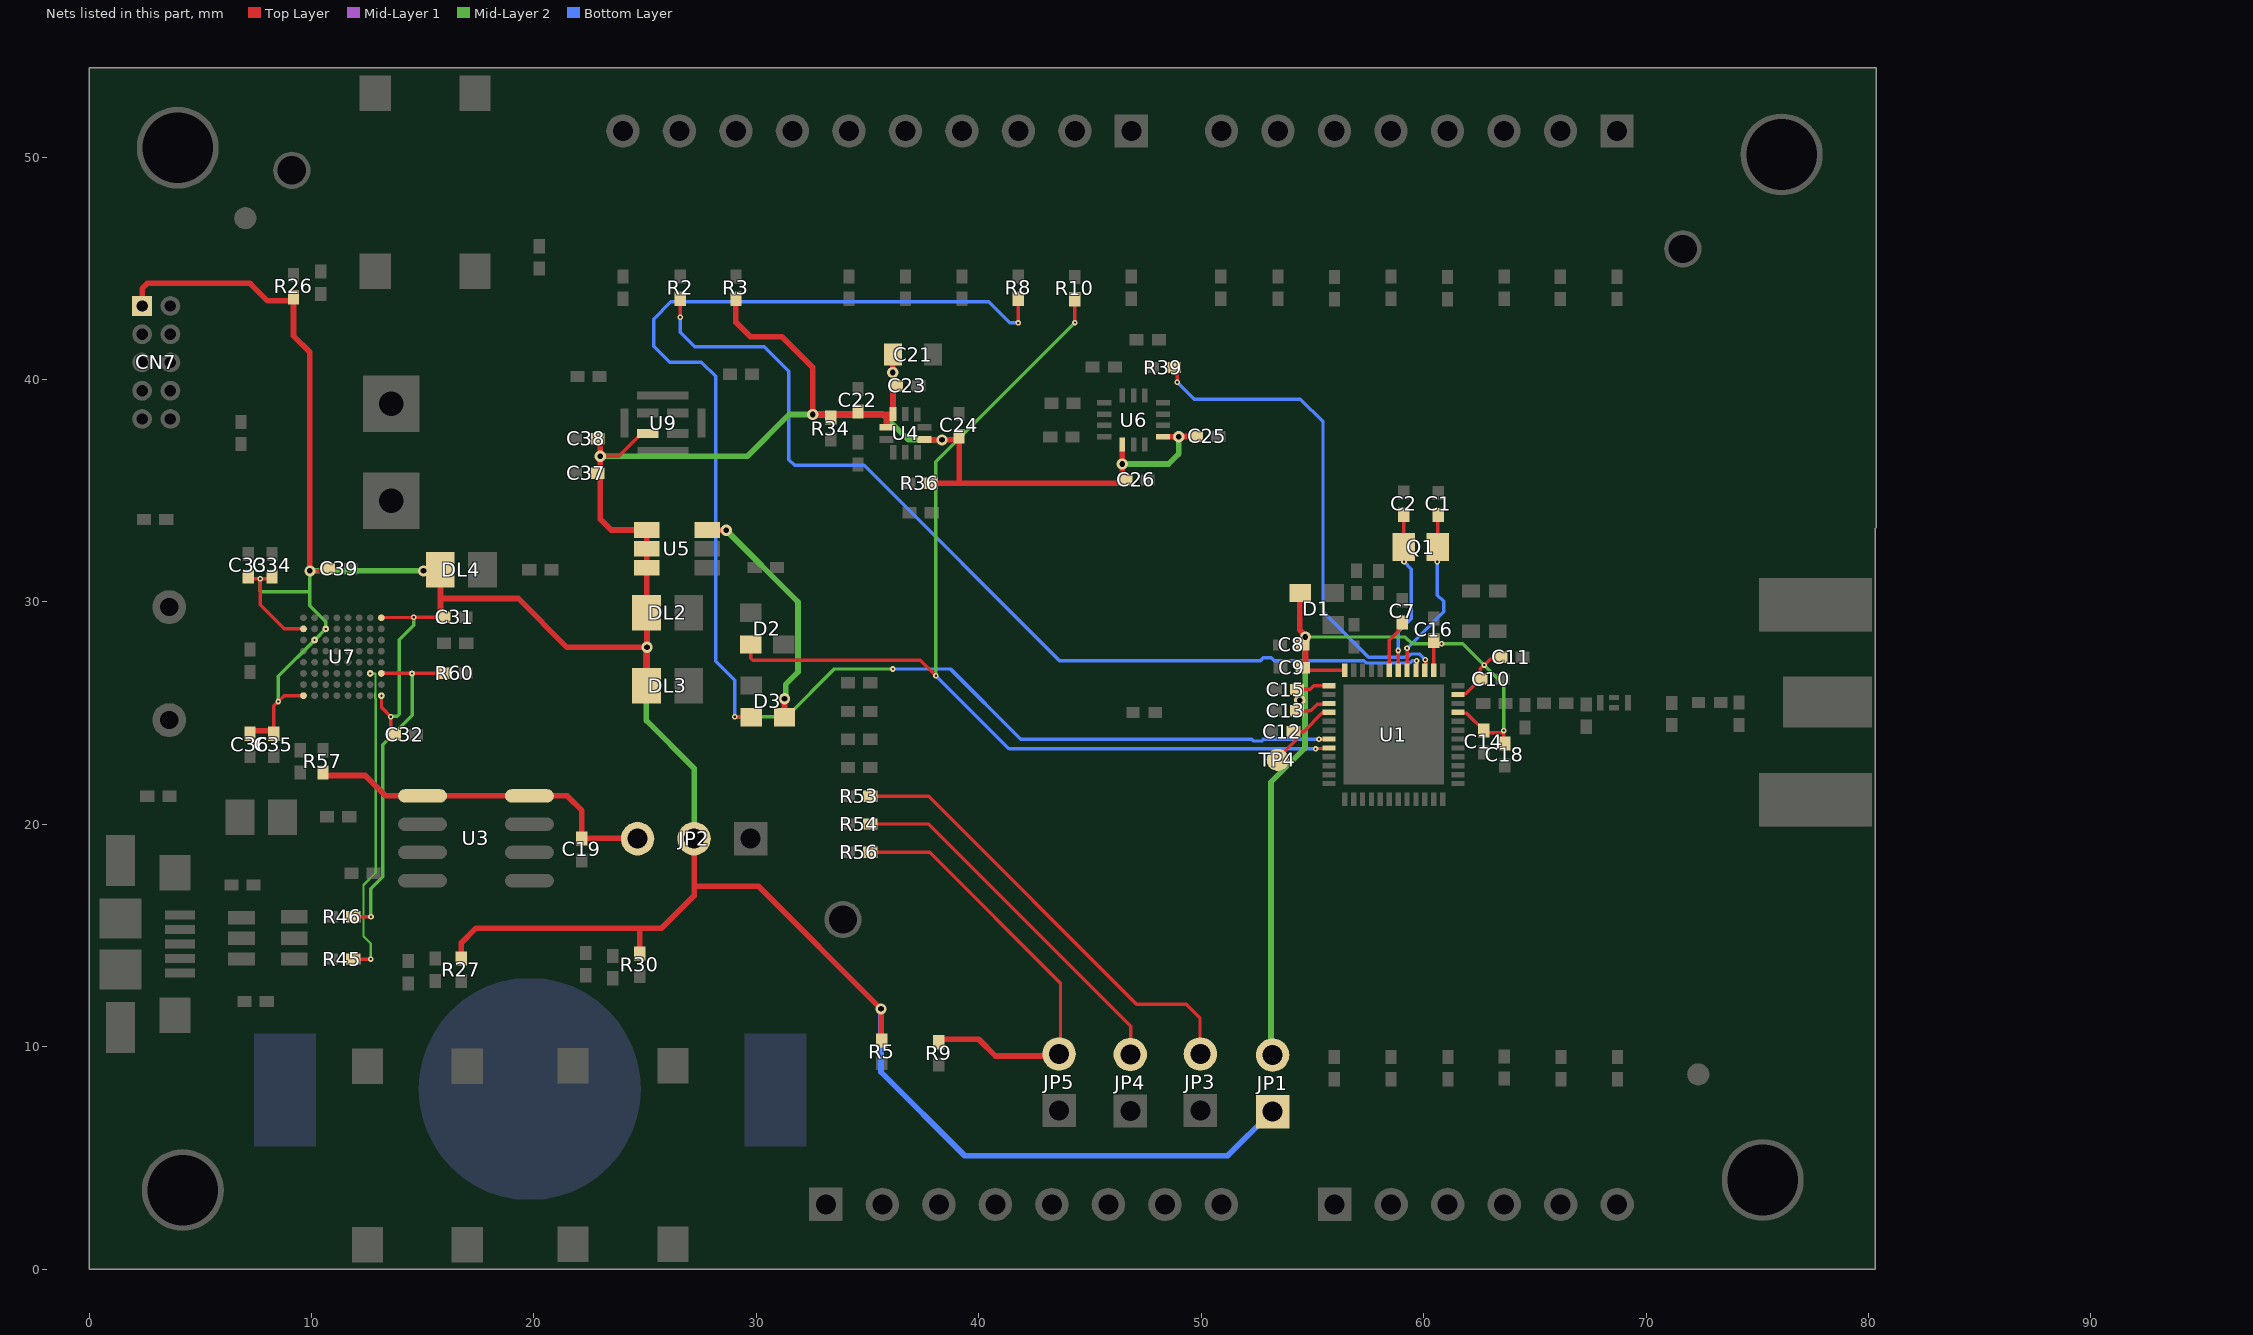
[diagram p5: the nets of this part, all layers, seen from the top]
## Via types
v1: diameter 0.508, hole 0.254, Top Layer to Bottom Layer, tented both sides, 518 vias
v2: diameter 0.254, hole 0.102, Top Layer to Bottom Layer, tented both sides, 128 vias

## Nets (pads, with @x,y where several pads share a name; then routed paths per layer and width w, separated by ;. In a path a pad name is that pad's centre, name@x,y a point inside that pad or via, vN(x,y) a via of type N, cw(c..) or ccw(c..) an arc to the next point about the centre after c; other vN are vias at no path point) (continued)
PB8: D2.1 R10.1 U1.44 | length 47.7
  Top Layer w0.152: D2.1@29.743,28.092 29.743,27.463 29.832,27.374 37.379,27.374 v2(38.074,26.678) ; v2(44.323,42.558) R10.1@44.323,43.472 ; v2(55.143,23.393) 55.163,23.413 55.722,23.413 U1.44@55.746,23.437
  Mid-Layer 2 w0.152: v2(38.074,26.678) 38.074,36.309 v2(44.323,42.558)
  Bottom Layer w0.152: v2(38.074,26.678) 41.359,23.393 v2(55.143,23.393)
PB9: D3.1 R8.1 U1.43 | length 68
  Top Layer w0.152: v2(29.032,24.841) D3.1@29.743,24.841 ; v2@41.783,42.553 R8.1@41.783,43.497 ; v2(55.296,23.825) 55.301,23.831 55.741,23.831 U1.43@55.746,23.836
  Top Layer w0.254: D3.1@29.743,24.841 D3.1@29.769,24.816 ; v2(41.775,42.545) v2@41.783,42.553
  Mid-Layer 2 w0.152: v2(29.032,24.841) 31.369,24.841 33.513,26.985 v2(36.142,26.985)
  Bottom Layer w0.152: v2(29.032,24.841) 29.032,26.486 28.176,27.342 28.176,40.14 27.534,40.782 26.104,40.782 25.387,41.499 25.387,42.719 26.158,43.49 40.452,43.49 41.397,42.545 v2(41.775,42.545) ; v2(36.142,26.985) 38.73,26.985 41.89,23.825 52.284,23.825 52.363,23.746 52.721,23.746 52.799,23.825 v2(55.296,23.825)
PB12: C2.2 Q1.1 U1.30 | length 7.2
  Top Layer w0.152: U1.30@58.856,26.927 v2(58.856,27.816) ; C2.2@59.108,33.785 Q1.1@59.108,32.469 59.12,32.457 v2(59.12,31.808)
  Bottom Layer w0.152: v2(58.856,27.816) 58.856,28.656 59.453,29.252 59.453,31.476 v2(59.12,31.808)
PB13: C1.2 Q1.2 U1.29 | length 7.8
  Top Layer w0.152: U1.29@59.257,26.927 v2(59.257,27.915) ; v2(60.616,31.808) 60.616,32.222 Q1.2@60.748,32.353 ; Q1.2@60.632,32.469 60.632,33.749 C1.2@60.653,33.769
  Top Layer w0.254: Q1.2@60.748,32.353 Q1.2@60.863,32.238
  Bottom Layer w0.152: v2(59.257,27.915) 60.899,29.557 60.899,30.024 60.616,30.306 v2(60.616,31.808)
PB14: R2.1 U1.28 | length 43.5
  Top Layer w0.152: v2(26.576,42.794) 26.576,43.492 R2.1@26.581,43.497 ; U1.28@59.657,26.927 59.684,26.954 v2(59.685,27.357)
  Bottom Layer w0.152: v2(26.576,42.794) 26.576,42.131 27.239,41.468 30.358,41.468 31.463,40.363 31.463,36.401 31.72,36.144 34.844,36.144 43.631,27.357 52.667,27.357 52.793,27.483 53.151,27.483 53.277,27.357 57.318,27.357 57.418,27.257 59.389,27.257 59.489,27.357 v2(59.685,27.357)
PB15: R39.2 U1.27 | length 22.6
  Top Layer w0.152: R39.2@48.92,40.538 48.923,40.536 v2(48.923,39.873) ; U1.27@60.057,26.927 60.1,26.97 60.1,27.378 v2(60.072,27.406)
  Bottom Layer w0.152: v2(48.923,39.873) 49.685,39.111 54.463,39.111 55.479,38.095 55.479,29.555 57.523,27.511 59.284,27.511 59.434,27.662 59.811,27.662 60.067,27.406 v2(60.072,27.406)
RED: D3.3 U5.6 | length 10.9
  Top Layer w0.152: U5.6@27.79,33.235 U5.6@27.802,33.223
  Top Layer w0.254: U5.6@27.802,33.223 v1(28.651,33.223) ; D3.3@31.267,24.816 v1(31.267,25.654)
  Mid-Layer 2 w0.254: v1(28.651,33.223) 31.877,29.997 31.877,26.848 31.316,26.287 31.316,25.703 v1(31.267,25.654)
RSTN: JP5.2 R9.2 R56.1 | length 19.9
  Top Layer w0.152: R56.1@35.255,18.745 37.795,18.745 43.675,12.865 JP5.2@43.675,9.588
  Top Layer w0.254: R9.2@38.202,10.338 40.002,10.338 40.752,9.588 JP5.2@43.675,9.588
SWCLK: JP3.2 R53.2 | length 20.5
  Top Layer w0.152: R53.2@35.255,21.26 37.744,21.26 47.092,11.913 49.327,11.913 49.949,11.29 JP3.2@49.949,9.614
  Mid-Layer 1 w0.254: JP3.2@49.936,9.614 JP3.2@49.949,9.614
SWDIO: JP4.2 R54.1 | length 16.7
  Top Layer w0.152: R54.1@35.255,20.015 37.744,20.015 46.838,10.922 JP4.2@46.838,9.576
USBDM: R46.1 R60.2 U7.C1 | length 15
  Top Layer w0.102: v2@14.521,26.787 v2(14.524,26.784) v2@14.536,26.797
  Top Layer w0.152: R46.1@12.014,15.85 12.017,15.847 v2(12.675,15.847) ; U7.C1@13.144,26.787 v2@14.521,26.787 ; v2@14.536,26.797 R60.2@15.799,26.797 ; R60.2@15.921,26.792 R60.2@15.926,26.797
  Mid-Layer 2 w0.152: v2(12.675,15.847) 12.675,17.104 13.208,17.638 13.208,23.589 14.524,24.905 v2(14.524,26.784)
USBDP: R45.1 U7.C2 | length 14.1
  Top Layer w0.152: R45.1@12.014,13.945 12.017,13.942 v2(12.67,13.942)
  Mid-Layer 2 w0.102: v2(12.644,26.787) 12.878,26.787 12.878,25.909 12.87,25.902 12.87,25.67 12.89,25.65 12.89,17.828 12.342,17.28 12.342,14.968 12.67,14.641 v2(12.67,13.942)
VCAP: C7.2 U1.31 | length 2.2
  Top Layer w0.152: U1.31@58.456,26.927 58.456,28.286 58.857,28.687 58.857,28.699 59.022,28.865 C7.2@59.035,28.865
VDD1: C8.2 C9.2 C10.2 C11.2 C13.2 C14.2 C15.2 C16.2 C18.2 D1.3 JP1.2 U1.21 U1.23 U1.26 U1.36 U1.37 U1.39 | length 48.1
  Top Layer w0.152: C13.2@54.432,25.121 54.447,25.105 54.917,25.105 55.218,25.406 55.716,25.406 U1.39@55.746,25.436 ; C15.2@54.46,26.073 54.905,26.073 55.068,26.237 U1.37@55.746,26.237 ; C9.2@54.699,27.038 54.811,26.927 U1.36@56.457,26.927 ; U1.26@60.457,26.927 60.457,28.115 60.454,28.118 v2(60.81,28.118) ; U1.21@61.547,25.036 61.576,25.008 61.927,25.008 C14.2@62.71,24.225 62.815,24.119 63.579,24.119 v2@63.6,24.141 ; U1.23@61.547,25.836 61.59,25.88 61.897,25.88 C10.2@62.549,26.532 62.549,26.988 v2(62.721,27.16) 62.991,27.43 63.366,27.43 C11.2@63.447,27.511 ; v2(63.6,24.215) v2@63.6,24.141 ; C18.2@63.646,23.639 63.6,23.685 v2@63.6,24.141
  Top Layer w0.254: C13.2@54.432,25.121 v1(54.432,25.578) C15.2@54.432,26.06 ; D1.3@54.432,30.395 54.432,28.745 54.686,28.491 v1(54.686,28.423) 54.686,28.067 54.693,28.061 54.693,27.045 C9.2@54.699,27.038
  Mid-Layer 2 w0.152: v1(54.686,28.423) 59.18,28.423 59.485,28.118 v2(60.81,28.118) 61.763,28.118 v2(62.721,27.16) 63.596,26.285 v2@63.596,24.123
  Mid-Layer 2 w0.254: JP1.2@53.137,9.588 53.137,21.9 54.666,23.429 54.666,25.578 v1(54.432,25.578) ; v1@54.681,25.578 54.686,25.578 v1(54.686,28.423)
VDD_1: C21.2 C22.2 C23.2 C24.2 C25.2 C26.2 C31.2 C32.2 C33.2 C34.2 C35.2 C36.2 C37.2 C38.2 C39.2 CN7.1 DL2.1 DL3.1 DL4.1 JP1.1 JP2.2 R3.1 R5.2 R26.1 R27.1 R30.1 R34.1 R36.1 U4.1 U4.6 U4.10 U5.1 U5.2 U5.3 U6.5 U6.8 U7.A1 U7.A8 U7.F7 U7.G6 U7.G8 U7.H1 U9.1 | length 192.1
  Top Layer w0.152: C33.2@7.163,31.013 7.188,31.039 v2(7.696,31.039) ; C34.2@8.23,31.013 8.204,31.039 v2(7.696,31.039) ; C35.2@8.306,24.206 8.306,25.324 v2(8.509,25.527) 8.768,25.786 9.606,25.786 U7.A8@9.677,25.857 ; U7.G8@9.642,28.788 8.778,28.788 7.696,29.87 v2(7.696,31.039) ; v1(9.931,31.394) 10.516,31.394 C39.2@10.617,31.496 ; v2(13.15,25.786) 13.15,25.255 v2(13.564,24.841) C32.2@13.564,24.028 ; U7.H1@13.15,29.289 13.161,29.3 14.571,29.3 v2@14.582,29.289 ; v2(14.605,29.312) C31.2@15.799,29.312 ; v1(22.987,36.551) 23.817,36.551 24.845,37.579 U9.1@25.121,37.579 ; DL2.1@25.07,29.515 DL2.1@25.082,29.502
  Top Layer w0.254: CN7.1@2.388,43.307 2.388,44.094 2.616,44.323 7.239,44.323 8.026,43.536 9.169,43.536 9.195,43.561 9.195,41.961 9.931,41.224 v1(9.931,31.394) ; C36.2@7.239,24.206 C35.2@8.306,24.206 ; v2@14.582,29.289 v2(14.605,29.312) ; v1(15.037,31.394) 15.799,31.394 15.799,30.152 ; C31.2@15.799,29.312 15.799,30.152 ; R27.1@16.739,14.097 16.739,14.677 17.395,15.334 23.894,15.334 ; C38.2@22.987,37.338 v1(22.987,36.551) 22.987,33.724 23.476,33.235 U5.1@25.07,33.235 U5.2@25.07,32.385 U5.3@25.07,31.535 DL2.1@25.07,29.515 ; 23.849,15.333 24.748,15.333 ; R30.1@24.765,14.326 24.765,15.333 25.747,15.333 27.203,16.789 JP2.2@27.203,19.355 JP2.2@27.203,19.406 ; DL3.1@25.069,26.238 25.082,26.251 v1(25.082,27.958) ; DL2.1@25.082,29.502 v1(25.082,27.958) ; 27.211,17.221 30.09,17.221 v1(35.608,11.703) 35.622,11.689 35.622,10.428 R5.2@35.636,10.414 ; R3.1@29.083,43.497 29.083,42.573 29.733,41.923 31.158,41.923 32.535,40.546 v1(32.535,38.425) 34.564,38.425 34.576,38.437 35.839,38.437 ; U4.1@35.852,37.859 35.852,38.424 35.839,38.437 ; C21.2@36.144,41.123 36.139,41.118 v1(36.139,40.315) 36.142,40.312 36.142,39.728 36.144,39.726 U4.10@36.144,38.443 36.138,38.437 35.839,38.437 ; U4.6@37.567,37.3 37.582,37.285 v1(38.346,37.285) 38.36,37.299 39.102,37.299 39.116,37.313 39.116,35.331 ; R36.1@37.973,35.331 39.116,35.331 ; U6.5@46.457,37.071 46.454,37.069 46.454,36.206 v1(46.452,36.203) 46.454,36.2 46.454,35.486 46.457,35.484 46.304,35.331 39.116,35.331 ; U6.8@48.285,37.427 U6.8@48.285,37.427 48.985,37.428 v1(48.986,37.429) 48.992,37.435 49.627,37.435 49.632,37.44 C25.2@49.614,37.457 ; 15.799,30.152 19.301,30.152 21.496,27.958 v1(25.082,27.958)
  Mid-Layer 2 w0.152: v2(7.696,31.039) 7.696,30.455 9.906,30.455 9.931,30.48 ; v2(8.509,25.527) 8.509,26.655 v2(10.142,28.288) v2(10.643,28.788) 10.643,29.108 9.931,29.82 9.931,30.48 ; v1@9.951,31.394 9.951,31.477 9.931,31.457 v1(9.931,31.394) 9.931,30.48 ; v2(13.564,24.841) 13.583,24.861 13.855,24.861 13.945,24.95 13.945,28.296 14.605,28.956 v2(14.605,29.312)
  Mid-Layer 2 w0.254: v1@9.951,31.394 v1(15.037,31.394) ; v1(22.987,36.551) 29.601,36.551 31.476,38.425 v1(32.535,38.425) 35.702,38.425 36.843,37.285 v1(38.346,37.285) ; v1(25.082,27.958) 25.057,27.932 25.057,24.668 27.203,22.522 JP2.2@27.203,19.406 ; v1(46.452,36.203) 48.537,36.203 48.986,36.652 v1(48.986,37.429)
  Bottom Layer w0.254: v1(35.608,11.703) 35.608,8.862 39.371,5.099 51.187,5.099 JP1.1@53.137,7.048
VDDA: C12.2 TP4.1 U1.40 | length 3.4
  Top Layer w0.152: TP4.1@53.447,22.898 53.447,22.98 54.279,23.812 54.279,24.168 54.607,24.168 55.475,25.036 U1.40@55.746,25.036
VLDO: C19.2 JP2.3 R57.2 U3.1 U3.8 | length 16.1
  Top Layer w0.254: R57.2@10.516,22.2 12.418,22.2 13.339,21.279 U3.1@14.997,21.279 U3.8@19.797,21.279 21.502,21.279 22.156,20.625 C19.2@22.156,19.373 24.646,19.373 JP2.3@24.663,19.355
pads on no net: CN2.1 CN2.5 CN2.8 CN6.4 Designator13.1 Designator14.1 U1.33 U1.41 U1.42 U4.7 U6.9 U6.10 U6.11 U7.A2 U7.A3 U7.B3 U7.B4 U7.B5 U7.B6 U7.B7 U7.B8 U7.C4 U7.C5 U7.C6 U7.C8 U7.D1 U7.D5 U7.D6 U7.E1 U7.E2 U7.E3 U7.E4 U7.E6 U7.E8 U7.F1 U7.F6 U7.F8 U7.G3 U7.H4 U7.H5 U7.H6

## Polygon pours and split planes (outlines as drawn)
no net on Top Overlay "-160559" (solid, pour order 0): 73.774,43.548 73.901,43.51 74.003,43.472 74.105,43.421 74.244,43.358 74.384,43.282 74.549,43.18 74.676,43.078 74.778,42.964 74.867,42.824 74.943,42.685 74.993,42.545 75.006,42.367 75.006,41.859 75.12,41.961 75.235,42.037 75.362,42.1 75.476,42.139 75.616,42.151 75.743,42.151 75.743,42.634 75.679,42.634 75.603,42.621 75.527,42.608 75.489,42.596 75.463,42.608 75.451,42.621 75.451,42.799 75.387,42.989 75.324,43.091 75.197,43.231 74.993,43.383 74.803,43.485 74.6,43.561 74.384,43.599 74.092,43.624 73.876,43.624 73.812,43.612 73.774,43.612 73.749,43.586 73.749,43.561
no net on Top Overlay "-160575" (solid, pour order 0): 72.06,43.218 72.136,43.167 72.263,43.129 72.39,43.078 72.568,43.015 72.72,42.951 72.911,42.862 73.063,42.786 73.215,42.697 73.393,42.57 73.533,42.456 73.711,42.278 73.825,42.139 73.914,41.974 74.016,41.758 74.079,41.542 74.092,41.275 74.092,40.488 74.168,40.564 74.295,40.665 74.435,40.767 74.663,40.881 74.892,40.957 75.032,40.983 75.032,41.554 74.943,41.542 74.841,41.504 74.778,41.478 74.739,41.453 74.727,41.465 74.714,41.605 74.701,41.821 74.689,41.948 74.638,42.1 74.549,42.266 74.447,42.418 74.219,42.659 74.003,42.837 73.825,42.964 73.635,43.066 73.381,43.155 73.139,43.231 72.949,43.269 72.606,43.282 72.326,43.282 72.2,43.269 72.111,43.243 72.06,43.231
no net on Top Overlay "-160574" (solid, pour order 0): 73.787,39.446 73.927,39.51 74.117,39.573 74.346,39.611 74.524,39.624 74.727,39.624 74.93,39.599 75.133,39.56 75.362,39.497 75.54,39.433 75.781,39.319 76.06,39.141 76.238,39.014 76.416,38.875 76.657,38.646 76.81,38.494 77,38.265 77.14,38.1 77.33,37.795 77.483,37.503 77.534,37.363 77.572,37.313 77.597,37.313 77.61,37.325 77.61,37.414 77.597,37.643 77.559,37.922 77.508,38.138 77.419,38.405 77.178,38.9 76.898,39.218 76.733,39.37 76.479,39.586 76.175,39.776 75.959,39.878 75.768,39.967 75.501,40.056 75.273,40.107 75.07,40.132 74.841,40.145 74.587,40.145 74.333,40.119 74.105,40.094 73.927,40.005 73.812,39.941 73.762,39.916 73.774,39.446
no net on Top Overlay "-160573" (solid, pour order 0): 70.383,42.405 70.434,42.393 70.498,42.38 70.625,42.342 70.815,42.278 71.006,42.215 71.171,42.151 71.45,42.024 71.615,41.948 71.882,41.808 72.149,41.631 72.39,41.427 72.555,41.262 72.72,41.084 72.809,40.945 72.898,40.767 73.038,40.424 73.088,40.17 73.114,39.84 73.127,39.535 73.114,39.116 73.101,38.938 73.266,39.065 73.393,39.179 73.482,39.256 73.66,39.383 73.774,39.446 73.774,39.916 73.698,39.878 73.685,39.891 73.698,40.183 73.673,40.411 73.609,40.691 73.508,40.957 73.368,41.212 73.228,41.415 73.088,41.58 72.949,41.719 72.707,41.935 72.466,42.088 72.212,42.24 71.92,42.367 71.666,42.456 71.323,42.52 71.095,42.545 70.841,42.532 70.612,42.507 70.434,42.469 70.371,42.443 70.371,42.418
no net on Top Overlay "-160571" (solid, pour order 0): 76.314,37.338 76.022,37.325 75.971,37.3 75.959,37.274 75.959,37.236 75.971,37.186 76.01,37.148 76.022,37.148 76.035,37.135 76.048,37.148 76.06,37.122 76.073,37.097 76.086,37.02 76.073,36.932 76.048,36.906 75.997,36.881 75.946,36.881 75.908,36.906 75.87,36.944 75.857,37.02 75.844,37.16 75.844,37.427 75.857,37.579 75.882,37.63 75.921,37.668 75.971,37.706 75.984,37.719 76.06,37.643 76.086,37.605 76.086,37.541 76.098,37.529 76.149,37.516 76.327,37.516 76.314,37.567 76.289,37.694 76.251,37.757 76.187,37.821 76.086,37.871 75.946,37.871 75.832,37.846 75.781,37.821 75.705,37.77 75.667,37.694 75.641,37.617 75.629,37.541 75.616,37.363 75.616,37.173 75.629,36.982 75.641,36.893 75.679,36.83 75.73,36.767 75.832,36.703 75.908,36.678 75.971,36.678 76.01,36.69 76.048,36.716 76.086,36.728 76.149,36.741 76.187,36.741 76.251,36.728 76.314,36.716
no net on Top Overlay "-160570" (solid, pour order 0): 74.765,37.452 74.765,37.846 74.879,37.846 75.146,37.833 75.311,37.821 75.374,37.795 75.425,37.744 75.451,37.681 75.463,37.617 75.476,37.516 75.476,37.452 75.235,37.452 75.248,37.503 75.248,37.541 75.235,37.592 75.184,37.643 75.12,37.668 74.993,37.668 74.993,37.452
no net on Top Overlay "-160569" (solid, pour order 0): 74.765,36.728 74.993,36.728 74.993,37.186 75.095,37.186 75.159,37.173 75.197,37.148 75.209,37.097 75.222,37.02 75.222,36.805 75.26,36.754 75.286,36.728 75.489,36.728 75.463,37.046 75.438,37.16 75.4,37.224 75.374,37.262 75.362,37.287 75.387,37.313 75.438,37.376 75.476,37.452 75.235,37.452 75.209,37.414 75.159,37.376 75.082,37.363 74.993,37.363 74.993,37.465 74.765,37.465
no net on Top Overlay "-160568" (solid, pour order 0): 74.079,36.728 73.876,36.728 73.876,37.846 74.066,37.846 74.117,37.833 74.155,37.795 74.27,37.465 74.346,37.249 74.358,37.211 74.397,37.211 74.409,37.236 74.409,37.846 74.612,37.846 74.612,36.728 74.346,36.728 74.143,37.338 74.117,37.363 74.092,37.363 74.079,37.351
no net on Top Overlay "-160567" (solid, pour order 0): 73.469,37.135 73.711,37.148 73.736,37.148 73.736,37.224 73.724,37.363 73.698,37.452 73.647,37.541 73.596,37.579 73.52,37.592 73.482,37.592 73.482,37.49 73.52,37.478 73.558,37.427 73.584,37.338 73.571,37.262 73.52,37.236 73.469,37.236
no net on Top Overlay "-160566" (solid, pour order 0): 73.571,36.893 73.596,36.932 73.609,36.97 73.635,36.995 73.685,37.008 73.711,36.995 73.724,36.982 73.724,36.957
no net on Top Overlay "-160565" (solid, pour order 0): 73.711,36.995 73.482,36.805 73.393,36.817 73.368,36.855 73.33,36.957 73.317,37.059 73.304,37.135 73.495,37.135 73.495,37.236 73.533,37.249 73.406,37.236 73.343,37.249 73.317,37.274 73.317,37.313 73.343,37.376 73.368,37.427 73.406,37.465 73.444,37.49 73.495,37.49 73.495,37.592 73.406,37.592 73.317,37.554 73.241,37.49 73.215,37.427 73.177,37.313 73.165,37.211 73.165,37.033 73.19,36.906 73.228,36.817 73.292,36.754 73.368,36.703 73.431,36.678 73.469,36.678 73.533,36.69 73.609,36.741 73.698,36.83 73.724,36.893 73.724,36.957 73.711,36.957
no net on Top Overlay "-160564" (solid, pour order 0): 72.479,37.567 72.606,37.567 72.606,37.071 72.619,36.944 72.619,36.868 72.657,36.83 72.707,36.817 72.758,36.817 72.796,36.843 72.847,36.893 72.86,36.982 72.86,37.148 72.873,37.554 73.012,37.567 73.012,36.716 72.974,36.728 72.911,36.741 72.873,36.728 72.822,36.716 72.784,36.703 72.746,36.69 72.695,36.678 72.619,36.69 72.555,36.728 72.504,36.792 72.492,36.83 72.479,36.919
no net on Top Overlay "-160563" (solid, pour order 0): 71.336,37.363 71.336,37.782 71.349,37.821 71.387,37.833 71.425,37.846 71.488,37.846 71.73,37.833 71.819,37.821 71.882,37.782 71.945,37.719 71.971,37.655 71.984,37.579 71.971,37.478 71.806,37.478 71.819,37.554 71.819,37.617 71.806,37.668 71.78,37.694 71.691,37.719 71.59,37.732 71.526,37.732 71.501,37.706 71.488,37.592 71.488,37.363
no net on Top Overlay "-160562" (solid, pour order 0): 71.349,36.741 71.603,36.728 71.704,36.728 71.819,36.741 71.895,36.779 71.971,36.855 72.009,36.932 72.022,37.033 72.022,37.071 71.996,37.16 71.958,37.224 71.907,37.274 71.857,37.313 71.92,37.376 71.958,37.44 71.971,37.478 71.806,37.478 71.78,37.414 71.73,37.376 71.666,37.363 71.336,37.363 71.336,37.211 71.488,37.211 71.488,37.236 71.666,37.236 71.73,37.224 71.78,37.198 71.831,37.135 71.857,37.084 71.869,37.02 71.844,36.944 71.806,36.893 71.768,36.855 71.717,36.83 71.488,36.83 71.488,37.211 71.336,37.211
no net on Top Overlay "-160561" (solid, pour order 0): 72.174,36.728 72.314,36.741 72.314,37.833 72.174,37.846
no net on Top Overlay "-160560" (solid, pour order 0): 75.73,42.151 75.882,42.139 76.048,42.1 76.213,42.024 76.391,41.91 76.53,41.796 76.632,41.694 76.759,41.554 76.873,41.402 76.975,41.237 77.064,41.059 77.102,40.996 77.114,40.996 77.14,41.021 77.127,41.224 77.102,41.402 77.064,41.554 77.025,41.656 76.886,41.897 76.746,42.075 76.67,42.164 76.543,42.278 76.403,42.393 76.289,42.469 76.213,42.52 76.022,42.583 75.895,42.621 75.794,42.634 75.73,42.634
no net on Top Overlay "-160558" (solid, pour order 0): 75.032,40.983 75.133,40.996 75.248,40.996 75.4,40.983 75.59,40.945 75.755,40.894 75.933,40.818 76.098,40.742 76.238,40.665 76.429,40.526 76.606,40.373 76.695,40.284 76.835,40.157 76.975,39.992 77.076,39.865 77.203,39.675 77.343,39.446 77.406,39.268 77.457,39.154 77.47,39.129 77.47,39.116 77.495,39.129 77.508,39.167 77.521,39.268 77.534,39.522 77.483,39.776 77.432,39.954 77.305,40.234 77.178,40.437 77.013,40.64 76.772,40.881 76.505,41.097 76.276,41.262 76.022,41.377 75.73,41.504 75.489,41.554 75.26,41.567 75.082,41.567 75.032,41.554
GND on Top Layer "Mid-Layer 1-GND" (solid, pour order 32): 0.114,54.14 80.125,54.14 80.125,36.623 55.994,36.623 55.994,33.599 47.181,33.599 47.181,15.037 79.934,15.037 79.944,0.114 0.114,0.114
GND_RF on Top Layer "Top Layer-GND_RF" (solid, pour order 26): 80.153,36.075 80.153,15.531 47.709,15.531 47.709,33.134 47.739,33.164 56.393,33.164 56.406,33.176 56.406,36.075
GND_RF on Top Layer "Top Layer-GND_RF 1" (solid, pour order 24): 61.68,30.839 61.68,28.339 63.78,28.339 63.78,30.839
no net on Top Layer "Top Layer-No Net" (solid, pour order 44): 80.38,29.057
GND on Top Layer "Top Layer-GND 1" (solid, pour order 12): -5.448,53.457
GND_RF on Mid-Layer 1 "Mid-Layer 1-GND_RF" (solid, pour order 4): 80.138,15.359 47.653,15.359 47.653,33.175 56.335,33.175 56.335,36.18 56.429,36.086 80.176,36.086
GND on Mid-Layer 1 "Mid-Layer 1-GND" (solid, pour order 34): 0.127,54.153 80.053,54.153 80.053,36.579 56.007,36.579 56.007,33.612 47.193,33.612 47.193,15.049 79.946,15.049 79.957,0.127 0.127,0.127
GND_RF on Bottom Layer "Bottom Layer-GND_RF" (solid, pour order 10): 80.155,15.348 47.727,15.348 47.727,32.88 56.136,32.88 56.136,35.884 56.23,35.79 80.192,35.79
GND on Bottom Layer "Bottom Layer-GND" (solid, pour order 20): 0.001,54.026 80.168,54.026 80.168,36.656 55.989,36.656 55.989,33.609 47.175,33.609 47.175,15.047 79.935,15.047 79.946,0 0.001,0
GND_RF on Mid-Layer 2 "Bottom Layer-GND_RF" (solid, pour order 30): 80.041,15.549 47.655,15.549 47.655,33.308 47.781,33.182 56.354,33.182 56.354,36.187 56.482,36.059 80.078,36.059
GND on Mid-Layer 2 "Mid-Layer 1-GND" (solid, pour order 36): 0.127,53.899 80.053,53.899 80.053,36.576 55.982,36.576 55.982,33.604 47.193,33.604 47.193,15.062 79.946,15.062 79.957,0.127 0.127,0.127

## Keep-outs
Keep-Out Layer:
  lines w0.026: 0,0 80.304,0 80.304,23.57 80.304,33.296 80.355,33.348 80.355,47.266 80.355,50.17 80.355,51.567 80.355,54.049 0,54.049 0,0

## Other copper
Top Layer:
  pour cut-out: 65.496,23.892
  pour cut-out: 62.263,25.102 62.277,25.088 64.802,25.088 64.802,24.054 64.296,24.054 63.477,24.054 62.939,24.592 62.491,24.587 62.491,24.611 62.143,24.959 62.263,25.078
  pour cut-out: 62.903,27.222 62.903,26.258 62.869,26.207 62.414,26.207 62.111,25.904 62.115,25.748 64.07,25.748 64.086,25.731 64.091,26.266 63.227,26.266 63.198,26.296 63.223,26.321 63.223,26.805 63.834,26.805 63.876,26.848 63.876,27.159 64.137,27.159 64.144,27.764 62.914,27.764
  pour cut-out: 61.171,26.668
  pour cut-out: 61.687,27.402 61.669,27.384 61.669,26.364 62.186,26.364 62.223,26.401 62.223,26.844 63.28,27.9 63.215,27.965 61.687,27.965
  region net NetC30_2: 61.841,25.555 62.014,25.595 62.478,25.693 62.478,25.187 62.284,25.226 61.842,25.318
  pour cut-out: 72.728,25.139 73.014,25.139 73.014,25.825 72.995,25.844 72.731,25.844
  pour cut-out: 65.777,25.093 66.063,25.093 66.063,25.779 66.044,25.798 65.78,25.798
  pour cut-out: 63.036,25.085 63.322,25.085 63.322,25.796 63.313,25.806 63.039,25.806
  region: 87.304,35.939
  region: 87.303,35.94
  pour cut-out: 53.975,23.698
  pour cut-out: 53.111,26.568 53.162,26.518 53.162,23.444 53.823,23.444 54.254,23.876 54.254,26.568
  pour cut-out: 58.522,35.027 58.523,35.025 58.523,33.205 61.09,33.205 61.059,33.236 61.059,35.034
  pour cut-out: 52.553,33.325 52.553,26.568 56.82,26.568 57.201,26.944 57.201,33.325
  pour cut-out: 61.68,30.172 63.78,30.179 63.78,29.091 61.68,29.091
  pour cut-out: 54.637,29.964 54.686,29.915 54.686,27.026 58.023,27.026 58.057,27.059 57.92,27.196 57.92,29.912 56.516,29.912 56.464,29.964
  pour cut-out: 58.523,35.631 61.059,35.631 61.059,31.732 58.14,31.732 58.14,31.013 61.542,31.013 61.542,35.966 56.363,35.966 56.363,31.125 58.523,31.125
  pour cut-out: 61.893,30.65 63.993,30.681 63.993,28.166 61.893,28.166 61.893,27.786 64.44,27.802 64.44,31.242 57.619,31.242 57.619,27.094 62.001,27.094
  pour cut-out: 95.039,39.675
  pour cut-out: 64.066,30.96 63.906,31.12 63.986,31.04
  pour cut-out: 63.986,31.04
  pour cut-out: 63.906,31.12 64.066,30.96
  region: 80.912,35.621

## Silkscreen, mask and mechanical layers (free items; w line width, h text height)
Top Overlay:
  drawing of 299 lines, arcs and shapes, not listed
  text "PA1" at 56.515,46.99 h0.95 r90
  text "PA7" at 54.229,46.863 h0.95 r90
  text "GND" at 32.131,46.736 h0.95 r90
  text "PB9" at 42.291,46.736 h0.95 r90
  text "PB8" at 44.958,46.736 h0.95 r90
  text "PA5" at 47.371,46.736 h0.95 r90
  text "PA4" at 51.435,46.736 h0.95 r90
  text "PA6" at 58.928,46.736 h0.95 r90
  text "PB0" at 64.008,46.736 h0.95 r90
  text "PA9" at 66.675,46.736 h0.95 r90
  text "PA8" at 69.215,46.736 h0.95 r90
  text "PA11" at 24.511,46.101 h0.95 r90
  text "PB14" at 27.178,46.101 h0.95 r90
  text "VBAT" at 29.591,45.974 h0.95 r90
  text "PA13" at 34.671,45.974 h0.95 r90
  text "PA14" at 37.211,45.974 h0.95 r90
  text "PA15" at 39.751,45.974 h0.95 r90
  text "PA13" at 61.468,45.974 h0.95 r90
  text "10" at 61.151,39.292 h0.95
  text ".Designator" at 61.254,38.284 h0.02
  text "O" at 15.951,37.579 h0.19
  text "O" at 23.905,36.6 h0.18
  text "W" at 52.89,36.608 h5.86
  text "O" at 24.765,33.782 h0.18
  text "FOR RESALE" at 45.594,26.899 h0.6 r90
  text "O" at 13.429,25.383 h0.18
  text "USB" at 25.019,21.031 h0.95 r90
  text "BAT" at 30.226,21.031 h0.95 r90
  text "O" at 55.756,20.639 h0.1
  text "STEVAL-IDB011V1" at 48.536,18.162 h1.14
  text "FOR EVALUATION ONLY" at 43.969,16.755 h0.6 r90
  text "NOT FCC APPROVED" at 45.582,16.743 h0.6 r90
  text "1" at 54.635,6.502 h0.57
  text "1" at 41.961,6.185 h0.57
  text "1" at 51.054,4.953 h0.57
  text "1" at 46.939,4.902 h0.57
  text "PB5" at 56.642,4.699 h0.95 r90
  text "VBAT" at 41.427,4.651 h0.95 r90
  text "VBAT" at 36.195,4.572 h0.95 r90
  text "RSTN" at 38.735,4.572 h0.95 r90
  text "PB2" at 59.055,4.572 h0.95 r90
  text "PB3" at 61.595,4.572 h0.95 r90
  text "PA12" at 64.135,4.572 h0.95 r90
  text "PB7" at 66.675,4.572 h0.95 r90
  text "PB4" at 69.215,4.572 h0.95 r90
  text "GND" at 43.942,4.343 h0.95
  text "GND" at 47.625,4.318 h0.95
Mechanical 1:
  lines w0.025: -0.013,0 ccw(c0,0) 0,-0.013 ; -0.013,0 ccw(c0,0) 0,-0.013 ; -0.013,0 -0.013,54.026 ; -0.013,54.026 cw(c0,54.026) 0,54.039 ; -0.013,54.026 cw(c0,54.026) 0,54.039 ; 0,-0.013 80.169,-0.013 ; 0,54.039 80.169,54.039 ; 80.169,-0.013 ccw(c80.169,0) 80.178,-0.009 ; 80.169,-0.013 ccw(c80.169,0) 80.178,-0.009 ; 80.169,54.039 cw(c80.169,54.026) 80.178,54.035 ; 80.169,54.039 cw(c80.169,54.026) 80.178,54.035 ; 80.178,-0.009 90.783,10.596 90.842,10.866 90.842,43.371 80.178,54.035 ; 0.013,0.013 80.163,0.013 90.822,10.671 90.822,43.355 80.163,54.013 0.013,54.013 0.013,0.013 ; 88.875,8.688 ccw(c88.866,8.697) 88.879,8.697 cw(c88.866,8.697) 88.875,8.688 ; 88.875,45.338 cw(c88.866,45.329) 88.879,45.329 ccw(c88.866,45.329) 88.875,45.338
Mechanical 13:
  lines w0.025: 13.391,25.33 13.641,25.58
Drill Drawing:
  lines w0.254: 7.023,-82.194 101.892,-82.194 ; 7.023,-82.067 7.023,-36.347 ; 7.023,-36.22 101.892,-36.22 ; 7.15,-76.987 101.765,-76.987 ; 7.15,-73.177 101.765,-73.177 ; 7.15,-69.367 101.765,-69.367 ; 7.15,-65.557 101.765,-65.557 ; 7.15,-61.747 101.765,-61.747 ; 7.15,-57.937 101.765,-57.937 ; 7.15,-54.127 101.765,-54.127 ; 7.15,-50.317 101.765,-50.317 ; 7.15,-46.507 101.765,-46.507 ; 7.15,-46.38 101.765,-46.38 ; 7.15,-41.427 101.765,-41.427 ; 7.15,-41.3 101.765,-41.3 ; 11.151,-63.652 12.421,-63.652 ; 11.151,-56.667 12.421,-55.397 ; 11.151,-55.397 12.421,-56.667 ; 11.151,-52.222 12.421,-52.222 ; 11.786,-64.287 11.786,-63.017 ; 11.786,-52.857 11.786,-51.587 ; 16.421,-76.987 16.421,-41.427 ; 16.548,-76.987 16.548,-41.427 ; 37.863,-76.987 37.863,-41.427 ; 58.352,-82.067 58.352,-41.427 ; 72.449,-82.067 72.449,-41.427 ; 101.892,-82.067 101.892,-36.347 ; 11.151,-68.097 11.151,-66.827 ; 11.151,-68.097 12.421,-68.097 ; 11.151,-68.097 12.421,-66.827 ; 11.151,-66.827 12.421,-66.827 ; 11.151,-66.827 12.421,-68.097 ; 12.421,-68.097 12.421,-66.827 ; 7.15,-82.067 101.765,-82.067 101.765,-36.347 7.15,-36.347 7.15,-82.067 ; 11.151,-75.336 11.151,-74.828 11.786,-75.463 12.421,-74.828 12.421,-75.336 11.786,-74.701 11.151,-75.336 ; 11.151,-71.272 11.786,-70.637 12.421,-71.272 11.786,-71.907 11.151,-71.272 ; 11.151,-59.842 11.151,-59.207 11.786,-59.207 11.786,-60.477 12.421,-60.477 12.421,-59.842 11.151,-59.842 ; 11.151,-52.857 11.151,-51.587 12.421,-51.587 12.421,-52.857 11.151,-52.857 ; 11.151,-48.666 11.151,-48.158 11.532,-47.777 12.04,-47.777 12.421,-48.158 12.421,-48.666 12.04,-49.047 11.532,-49.047 11.151,-48.666
  text ".Legend" at 7.15,-36.347 h0.64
